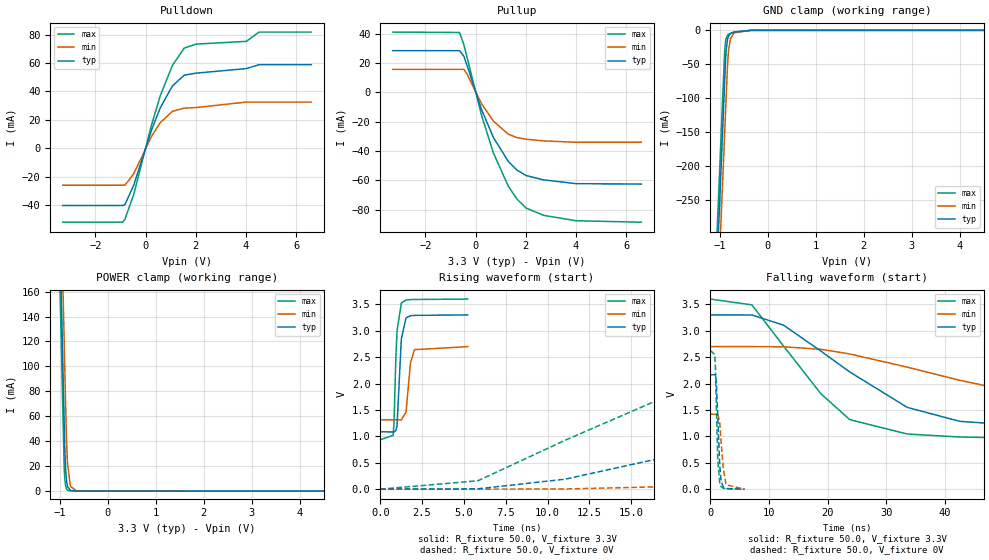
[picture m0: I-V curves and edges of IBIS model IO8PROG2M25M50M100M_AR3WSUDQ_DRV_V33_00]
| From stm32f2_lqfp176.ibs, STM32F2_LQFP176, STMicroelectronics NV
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| *** New cell (Generated with 5.14beta1 (Sep 20 2010 13:23:23))
[Model]   IO8PROG2M25M50M100M_AR3WSUDQ_DRV_V33_00
Model_type 3-state
Polarity   Non-Inverting
Enable   Active-Low
| CAP_THRESHOLD on pad IOV33 is "CMOS" :
| Rising=10.0% of vddio   Falling=90.0% of vddio
| C_comp min and max val. don't necessarily correlate with the min and max pvt
| but are the smallest and greatest pad capacitance found.
| var   typ   min   max
C_comp   2.51835pF  2.40460pF  2.66130pF
Vmeas = 1.65V   | Reference voltage for timing measurements
Cref  = 50.0pF   | Timing specification test load capacitance value
Rref  = 1.0MOhm   | Timing specification test load resistance value
Vref  = 1.65V   | Timing specification test load voltage
[Model Spec]
| variable   typ   min   max
[Temperature Range] 25.0 125.0 -40.0
| variable   typ   min   max
[Voltage Range] 3.3V 2.7V 3.6V
| variable   typ   min   max
[POWER Clamp Reference] 3.3V 2.7V 3.6V
| variable   typ   min   max
[GND Clamp Reference] 0V 0V 0V
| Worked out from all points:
|   slope of the pulldown table from 0 to 0.495 V, typ, clamps not added: 20 ohm
|   slope of the pullup table from 0 to 0.495 V, typ, clamps not added: 21.7 ohm
|   GND clamp passes 1 mA (typ) near -0.59 V on its own axis
|   POWER clamp passes 1 mA (typ) near -0.81 V on its own axis
|   rising waveform, R_fixture 50.0, V_fixture 3.3V: 20-80 % time 185ps typ, 224ps min, 174ps max; typ from 1.09 V to 3.3 V
|   falling waveform, R_fixture 50.0, V_fixture 3.3V: 20-80 % time 18.1ns typ, 35.5ns min, 11.7ns max; typ from 3.3 V to 1.09 V
|   rising waveform, R_fixture 50.0, V_fixture 0V: 20-80 % time 19.4ns typ, 44ns min, 10.8ns max; typ from 0 V to 2.17 V
|   falling waveform, R_fixture 50.0, V_fixture 0V: 20-80 % time 445ps typ, 629ps min, 359ps max; typ from 2.17 V to 0.001 V
[POWER Clamp]
-3.3V     4.117A     4.183A     4.076A
-1.09V    360mA      425.6mA    319.3mA
-1.05V    292mA      357.6mA    251.3mA
-1.01V    224mA      289.6mA    183.3mA
-910mV    53.96mA    119.6mA    18.43mA
-900mV    36.96mA    102.6mA    11.2mA
-880mV    16.97mA    68.61mA    4.141mA
-860mV    7.791mA    38.56mA    1.53mA
-840mV    3.577mA    21.53mA    565.5uA
-780mV    346.2uA    3.745mA    28.55uA
-660mV    3.242uA    113.2uA    73.21nA
6.6V      0A         0A         0A
[GND Clamp]
-3.3V     -4.156A    -4.231A    -4.108A
-1.06V    -347.5mA   -423.2mA   -300.1mA
-940mV    -143.5mA   -219.2mA   -96.09mA
-900mV    -75.54mA   -151.2mA   -30.39mA
-880mV    -41.78mA   -117.2mA   -15.62mA
-870mV    -30.28mA   -100.2mA   -12.04mA
-840mV    -13.1mA    -50.87mA   -7.186mA
-820mV    -8.54mA    -30.65mA   -5.881mA
-780mV    -4.86mA    -12.37mA   -4.416mA
-700mV    -2.552mA   -3.603mA   -2.454mA
-350mV    -11.93uA   -60.06uA   -2.46uA
6.6V      10.25nA    1.32uA     122.8pA
| variable   typ   min   max
[Pullup Reference] 3.3V 2.7V 3.6V
| variable   typ   min   max
[Pulldown Reference] 0V 0V 0V
[Pullup]
-3.3V     28.36mA    15.61mA    40.98mA
-640mV    28.36mA    15.61mA    40.72mA
-470mV    24.68mA    15.55mA    32.6mA
-350mV    18.69mA    12.65mA    24.51mA
240mV     -11.89mA   -7.822mA   -15.87mA
710mV     -30.8mA    -19.68mA   -41.36mA
1.3V      -47.02mA   -28.56mA   -63.9mA
1.65V     -53.05mA   -30.92mA   -72.82mA
2.01V     -56.71mA   -31.98mA   -78.86mA
2.7V      -59.67mA   -33.14mA   -83.8mA
4.01V     -62.27mA   -34.07mA   -87.53mA
6.6V      -62.54mA   -34.07mA   -88.51mA
[Pulldown]
-3.3V     -40.26mA   -25.94mA   -51.99mA
-910mV    -40.26mA   -25.94mA   -51.99mA
-820mV    -39.59mA   -25.94mA   -49.78mA
-470mV    -25.89mA   -17.87mA   -32.39mA
240mV     12.97mA    8.52mA     16.62mA
590mV     28.62mA    18.11mA    37.2mA
1.07V     43.85mA    26mA       58.31mA
1.54V     51.42mA    28.24mA    70.48mA
2.01V     52.82mA    28.63mA    73.27mA
4.01V     56.04mA    32.48mA    75.18mA
4.52V     58.77mA    32.48mA    81.71mA
6.6V      58.77mA    32.48mA    81.71mA
[Ramp]
dV/dt_r 1.29886V/19.39239ns 851.12089mV/43.96601ns 1.57727V/10.7657ns
dV/dt_f 1.3278V/18.13996ns 831.27765mV/35.53844ns 1.59819V/11.74015ns
R_load = 50.0
| Removed startup time: 0s 0s 0s  .
| Removed end time: 5.224ns.
[Rising Waveform]
R_fixture   = 50.0
V_fixture   = 3.3V
V_fixture_min = 2.7V
V_fixture_max = 3.6V
0s        1.087V     1.314V     936.3mV
768ps     1.084V     1.314V     1.018V
822ps     1.083V     1.314V     1.265V
930ps     1.111V     1.314V     2.478V
1.002ns   1.199V     1.313V     2.995V
1.258ns   2.844V     1.309V     3.523V
1.54ns    3.243V     1.461V     3.581V
1.806ns   3.283V     2.394V     3.589V
2.044ns   3.29V      2.641V     3.591V
5.228ns   3.299V     2.699V     3.599V
| Removed startup time: 0s 0s 0s  .
| Removed end time: 251.76ns.
[Falling Waveform]
R_fixture   = 50.0
V_fixture   = 3.3V
V_fixture_min = 2.7V
V_fixture_max = 3.6V
0s        3.3V       2.7V       3.6V
7.08ns    3.299V     2.7V       3.49V
12.48ns   3.106V     2.697V     2.711V
18.84ns   2.615V     2.649V     1.808V
23.76ns   2.22V      2.561V     1.317V
33.56ns   1.549V     2.311V     1.045V
42.52ns   1.285V     2.062V     988.4mV
58.56ns   1.161V     1.682V     953.6mV
84.6ns    1.107V     1.444V     940mV
251.8ns   1.087V     1.315V     936.3mV
| Removed startup time: 0s 0s 0s  .
| Removed end time: 243.32ns.
[Rising Waveform]
R_fixture   = 50.0
V_fixture   = 0V
V_fixture_min = 0V
V_fixture_max = 0V
0s        8.519nV    394.5nV    5.738nV
5.84ns    6.699mV    -105uV     159mV
11.08ns   190.1mV    4.116mV    929.7mV
20.44ns   843.7mV    72.35mV    2.215V
30.84ns   1.552V     251.2mV    2.546V
37.6ns    1.864V     394.3mV    2.593V
47.12ns   2.037V     608.8mV    2.617V
68.16ns   2.137V     1.023V     2.627V
93.68ns   2.159V     1.285V     2.629V
243.4ns   2.165V     1.419V     2.629V
| Removed startup time: 0s 0s 0s  .
| Removed end time: 5.82ns.
[Falling Waveform]
R_fixture   = 50.0
V_fixture   = 0V
V_fixture_min = 0V
V_fixture_max = 0V
0s        2.165V     1.419V     2.629V
770ps     2.17V      1.418V     2.548V
882ps     2.166V     1.418V     2.268V
1.038ns   2.031V     1.42V      1.555V
1.28ns    1.371V     1.428V     539.8mV
1.616ns   435.4mV    1.255V     114.2mV
1.84ns    163.9mV    915mV      49.43mV
2.206ns   43.97mV    407.4mV    17.94mV
2.688ns   13mV       83.41mV    9.189mV
5.824ns   1.034mV    941.9uV    976.4uV
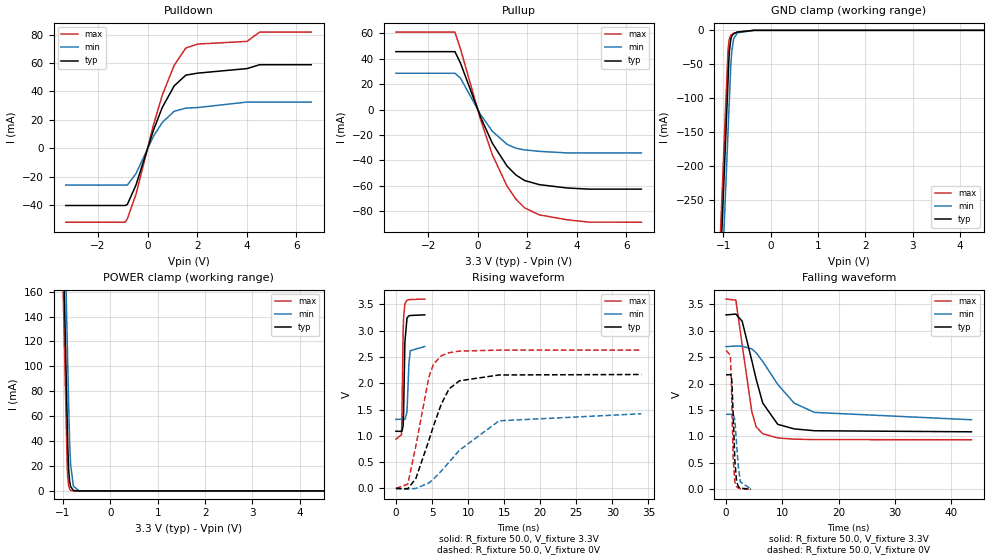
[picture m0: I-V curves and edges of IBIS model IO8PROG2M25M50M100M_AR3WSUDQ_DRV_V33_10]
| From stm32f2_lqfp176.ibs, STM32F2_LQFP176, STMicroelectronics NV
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| *** New cell (Generated with 5.14beta1 (Sep 20 2010 13:23:23))
[Model]   IO8PROG2M25M50M100M_AR3WSUDQ_DRV_V33_10
Model_type 3-state
Polarity   Non-Inverting
Enable   Active-Low
| CAP_THRESHOLD on pad IOV33 is "CMOS" :
| Rising=10.0% of vddio   Falling=90.0% of vddio
| C_comp min and max val. don't necessarily correlate with the min and max pvt
| but are the smallest and greatest pad capacitance found.
| var   typ   min   max
C_comp   2.51835pF  2.40460pF  2.66130pF
Vmeas = 1.65V   | Reference voltage for timing measurements
Cref  = 50.0pF   | Timing specification test load capacitance value
Rref  = 1.0MOhm   | Timing specification test load resistance value
Vref  = 1.65V   | Timing specification test load voltage
[Model Spec]
| variable   typ   min   max
[Temperature Range] 25.0 125.0 -40.0
| variable   typ   min   max
[Voltage Range] 3.3V 2.7V 3.6V
| variable   typ   min   max
[POWER Clamp Reference] 3.3V 2.7V 3.6V
| variable   typ   min   max
[GND Clamp Reference] 0V 0V 0V
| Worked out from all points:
|   slope of the pulldown table from 0 to 0.495 V, typ, clamps not added: 20 ohm
|   slope of the pullup table from 0 to 0.495 V, typ, clamps not added: 21.7 ohm
|   GND clamp passes 1 mA (typ) near -0.59 V on its own axis
|   POWER clamp passes 1 mA (typ) near -0.81 V on its own axis
|   rising waveform, R_fixture 50.0, V_fixture 3.3V: 20-80 % time 185ps typ, 224ps min, 175ps max; typ from 1.09 V to 3.3 V
|   falling waveform, R_fixture 50.0, V_fixture 3.3V: 20-80 % time 3.18ns typ, 6.14ns min, 2.09ns max; typ from 3.3 V to 1.09 V
|   rising waveform, R_fixture 50.0, V_fixture 0V: 20-80 % time 3.25ns typ, 6.06ns min, 2.15ns max; typ from 0 V to 2.17 V
|   falling waveform, R_fixture 50.0, V_fixture 0V: 20-80 % time 445ps typ, 628ps min, 360ps max; typ from 2.17 V to 0.001 V
[POWER Clamp]
-3.3V     4.117A     4.183A     4.076A
-1.09V    360mA      425.6mA    319.3mA
-1.05V    292mA      357.6mA    251.3mA
-1.01V    224mA      289.6mA    183.3mA
-910mV    53.96mA    119.6mA    18.43mA
-900mV    36.96mA    102.6mA    11.2mA
-880mV    16.97mA    68.61mA    4.141mA
-860mV    7.791mA    38.56mA    1.53mA
-840mV    3.577mA    21.53mA    565.5uA
-780mV    346.2uA    3.745mA    28.55uA
-660mV    3.242uA    113.2uA    73.21nA
6.6V      0A         0A         0A
[GND Clamp]
-3.3V     -4.156A    -4.231A    -4.108A
-1.06V    -347.5mA   -423.2mA   -300.1mA
-940mV    -143.5mA   -219.2mA   -96.09mA
-900mV    -75.54mA   -151.2mA   -30.39mA
-880mV    -41.78mA   -117.2mA   -15.62mA
-870mV    -30.28mA   -100.2mA   -12.04mA
-840mV    -13.1mA    -50.87mA   -7.186mA
-820mV    -8.54mA    -30.65mA   -5.881mA
-780mV    -4.86mA    -12.37mA   -4.416mA
-700mV    -2.552mA   -3.603mA   -2.454mA
-350mV    -11.93uA   -60.06uA   -2.46uA
6.6V      10.25nA    1.32uA     122.8pA
| variable   typ   min   max
[Pullup Reference] 3.3V 2.7V 3.6V
| variable   typ   min   max
[Pulldown Reference] 0V 0V 0V
[Pullup]
-3.3V     45.5mA     28.54mA    60.89mA
-920mV    45.5mA     28.54mA    60.89mA
-700mV    36.73mA    24.81mA    47.95mA
120mV     -6.142mA   -4.065mA   -8.189mA
590mV     -26.5mA    -17.07mA   -35.52mA
1.18V     -44.36mA   -27.27mA   -60.11mA
1.54V     -51.43mA   -30.39mA   -70.35mA
1.89V     -55.75mA   -31.69mA   -77.18mA
2.48V     -58.98mA   -32.83mA   -82.75mA
3.6V      -61.62mA   -34.07mA   -86.61mA
4.49V     -62.54mA   -34.07mA   -88.47mA
6.6V      -62.54mA   -34.07mA   -88.51mA
[Pulldown]
-3.3V     -40.26mA   -25.94mA   -51.99mA
-910mV    -40.26mA   -25.94mA   -51.99mA
-820mV    -39.59mA   -25.94mA   -49.78mA
-470mV    -25.89mA   -17.87mA   -32.39mA
240mV     12.97mA    8.52mA     16.62mA
590mV     28.62mA    18.11mA    37.2mA
1.07V     43.85mA    26mA       58.31mA
1.54V     51.42mA    28.24mA    70.48mA
2.01V     52.82mA    28.63mA    73.27mA
4.01V     56.04mA    32.48mA    75.18mA
4.52V     58.77mA    32.48mA    81.71mA
6.6V      58.77mA    32.48mA    81.71mA
[Ramp]
dV/dt_r 1.29886V/3.25391ns 851.30591mV/6.06174ns 1.57727V/2.15285ns
dV/dt_f 1.32782V/3.18087ns 831.60152mV/6.14857ns 1.59819V/2.0877ns
R_load = 50.0
| Removed startup time: 0s 0s 0s  .
| Removed end time: 3.993ns.
[Rising Waveform]
R_fixture   = 50.0
V_fixture   = 3.3V
V_fixture_min = 2.7V
V_fixture_max = 3.6V
0s        1.087V     1.314V     936.3mV
769ps     1.084V     1.314V     1.02V
823ps     1.083V     1.314V     1.275V
997ps     1.189V     1.313V     2.967V
1.066ns   1.46V      1.313V     3.244V
1.242ns   2.778V     1.309V     3.509V
1.536ns   3.239V     1.454V     3.577V
1.799ns   3.28V      2.377V     3.585V
1.992ns   3.286V     2.618V     3.589V
3.995ns   3.298V     2.697V     3.598V
| Removed startup time: 0s 0s 0s  .
| Removed end time: 43.615ns.
[Falling Waveform]
R_fixture   = 50.0
V_fixture   = 3.3V
V_fixture_min = 2.7V
V_fixture_max = 3.6V
0s        3.3V       2.7V       3.6V
1.745ns   3.316V     2.711V     3.58V
2.865ns   3.181V     2.707V     2.734V
4.58ns    2.435V     2.657V     1.467V
5.345ns   2.087V     2.583V     1.181V
6.515ns   1.633V     2.419V     1.051V
9.185ns   1.229V     1.985V     970.5mV
12.11ns   1.142V     1.629V     947.7mV
15.74ns   1.107V     1.454V     939.6mV
43.63ns   1.087V     1.315V     936.3mV
| Removed startup time: 0s 0s 0s  .
| Removed end time: 33.995ns.
[Rising Waveform]
R_fixture   = 50.0
V_fixture   = 0V
V_fixture_min = 0V
V_fixture_max = 0V
0s        8.508nV    394.6nV    5.727nV
1.64ns    -4.182mV   -13.42mV   81.4mV
2.755ns   186.5mV    726.8uV    802.5mV
4.55ns    905.9mV    102.6mV    2.11V
5.21ns    1.189V     179.3mV    2.365V
6.28ns    1.6V       329.6mV    2.52V
7.35ns    1.889V     497.1mV    2.578V
8.795ns   2.045V     726.1mV    2.61V
14.29ns   2.156V     1.285V     2.628V
34.01ns   2.165V     1.419V     2.629V
| Removed startup time: 0s 0s 0s  .
| Removed end time: 4.439ns.
[Falling Waveform]
R_fixture   = 50.0
V_fixture   = 0V
V_fixture_min = 0V
V_fixture_max = 0V
0s        2.165V     1.419V     2.629V
779ps     2.17V      1.418V     2.532V
943ps     2.14V      1.419V     2.038V
1.035ns   2.034V     1.42V      1.569V
1.267ns   1.413V     1.427V     577.9mV
1.564ns   543.1mV    1.314V     142.9mV
1.862ns   150.9mV    877.4mV    48.17mV
2.197ns   46.75mV    416.2mV    20.44mV
2.544ns   19.06mV    138.6mV    9.23mV
4.441ns   1.497mV    2.846mV    977.3uV
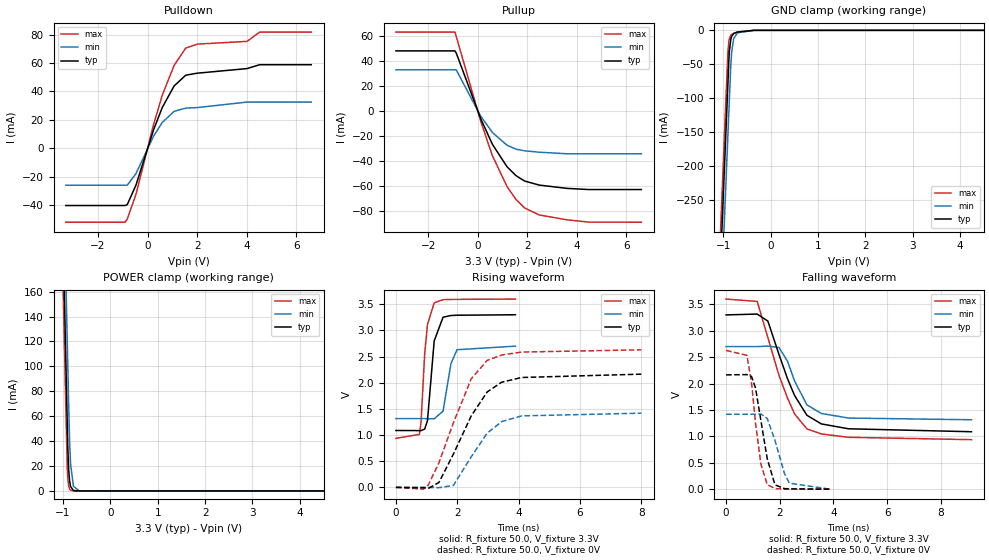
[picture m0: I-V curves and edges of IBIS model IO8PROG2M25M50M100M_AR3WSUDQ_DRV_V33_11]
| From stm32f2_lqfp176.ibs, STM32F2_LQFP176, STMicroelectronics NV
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| *** New cell (Generated with 5.14beta1 (Sep 20 2010 13:23:23))
[Model]   IO8PROG2M25M50M100M_AR3WSUDQ_DRV_V33_11
Model_type 3-state
Polarity   Non-Inverting
Enable   Active-Low
| CAP_THRESHOLD on pad IOV33 is "CMOS" :
| Rising=10.0% of vddio   Falling=90.0% of vddio
| C_comp min and max val. don't necessarily correlate with the min and max pvt
| but are the smallest and greatest pad capacitance found.
| var   typ   min   max
C_comp   2.51835pF  2.40455pF  2.66130pF
Vmeas = 1.65V   | Reference voltage for timing measurements
Cref  = 50.0pF   | Timing specification test load capacitance value
Rref  = 1.0MOhm   | Timing specification test load resistance value
Vref  = 1.65V   | Timing specification test load voltage
[Model Spec]
| variable   typ   min   max
[Temperature Range] 25.0 125.0 -40.0
| variable   typ   min   max
[Voltage Range] 3.3V 2.7V 3.6V
| variable   typ   min   max
[POWER Clamp Reference] 3.3V 2.7V 3.6V
| variable   typ   min   max
[GND Clamp Reference] 0V 0V 0V
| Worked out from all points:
|   slope of the pulldown table from 0 to 0.495 V, typ, clamps not added: 20 ohm
|   slope of the pullup table from 0 to 0.495 V, typ, clamps not added: 21.7 ohm
|   GND clamp passes 1 mA (typ) near -0.59 V on its own axis
|   POWER clamp passes 1 mA (typ) near -0.81 V on its own axis
|   rising waveform, R_fixture 50.0, V_fixture 3.3V: 20-80 % time 188ps typ, 225ps min, 176ps max; typ from 1.09 V to 3.3 V
|   falling waveform, R_fixture 50.0, V_fixture 3.3V: 20-80 % time 1.04ns typ, 731ps min, 1.05ns max; typ from 3.3 V to 1.09 V
|   rising waveform, R_fixture 50.0, V_fixture 0V: 20-80 % time 1.12ns typ, 970ps min, 1.04ns max; typ from 0 V to 2.16 V
|   falling waveform, R_fixture 50.0, V_fixture 0V: 20-80 % time 420ps typ, 489ps min, 355ps max; typ from 2.17 V to 0.001 V
[POWER Clamp]
-3.3V     4.117A     4.183A     4.076A
-1.09V    360mA      425.6mA    319.3mA
-1.05V    292mA      357.6mA    251.3mA
-1.01V    224mA      289.6mA    183.3mA
-910mV    53.96mA    119.6mA    18.43mA
-900mV    36.96mA    102.6mA    11.2mA
-880mV    16.97mA    68.61mA    4.141mA
-860mV    7.791mA    38.56mA    1.53mA
-840mV    3.577mA    21.53mA    565.5uA
-780mV    346.2uA    3.745mA    28.55uA
-660mV    3.242uA    113.2uA    73.21nA
6.6V      0A         0A         0A
[GND Clamp]
-3.3V     -4.156A    -4.231A    -4.108A
-1.06V    -347.5mA   -423.2mA   -300.1mA
-940mV    -143.5mA   -219.2mA   -96.09mA
-900mV    -75.54mA   -151.2mA   -30.39mA
-880mV    -41.78mA   -117.2mA   -15.62mA
-870mV    -30.28mA   -100.2mA   -12.04mA
-840mV    -13.1mA    -50.87mA   -7.186mA
-820mV    -8.54mA    -30.65mA   -5.881mA
-780mV    -4.86mA    -12.37mA   -4.416mA
-700mV    -2.552mA   -3.603mA   -2.454mA
-350mV    -11.93uA   -60.06uA   -2.46uA
6.6V      10.25nA    1.32uA     122.8pA
| variable   typ   min   max
[Pullup Reference] 3.3V 2.7V 3.6V
| variable   typ   min   max
[Pulldown Reference] 0V 0V 0V
[Pullup]
-3.3V     47.82mA    32.75mA    62.76mA
-920mV    47.82mA    32.75mA    62.76mA
-870mV    46.26mA    32.75mA    59.5mA
120mV     -6.142mA   -4.065mA   -8.189mA
590mV     -26.5mA    -17.07mA   -35.52mA
1.18V     -44.36mA   -27.27mA   -60.11mA
1.54V     -51.43mA   -30.39mA   -70.35mA
1.89V     -55.75mA   -31.69mA   -77.18mA
2.48V     -58.98mA   -32.83mA   -82.75mA
3.6V      -61.62mA   -34.07mA   -86.61mA
4.49V     -62.54mA   -34.07mA   -88.47mA
6.6V      -62.54mA   -34.07mA   -88.51mA
[Pulldown]
-3.3V     -40.26mA   -25.94mA   -51.99mA
-910mV    -40.26mA   -25.94mA   -51.99mA
-820mV    -39.59mA   -25.94mA   -49.78mA
-470mV    -25.89mA   -17.87mA   -32.39mA
240mV     12.97mA    8.52mA     16.62mA
590mV     28.62mA    18.11mA    37.2mA
1.07V     43.85mA    26mA       58.31mA
1.54V     51.42mA    28.24mA    70.48mA
2.01V     52.82mA    28.63mA    73.27mA
4.01V     56.04mA    32.48mA    75.18mA
4.52V     58.77mA    32.48mA    81.71mA
6.6V      58.77mA    32.48mA    81.71mA
[Ramp]
dV/dt_r 1.29886V/1.12517ns 851.30674mV/971.89074ps 1.57727V/1.04388ns
dV/dt_f 1.32782V/1.03911ns 831.60268mV/731.70994ps 1.59819V/1.05301ns
R_load = 50.0
| Removed startup time: 0s 0s 0s  .
| Removed end time: 3.893ns.
[Rising Waveform]
R_fixture   = 50.0
V_fixture   = 3.3V
V_fixture_min = 2.7V
V_fixture_max = 3.6V
0s        1.087V     1.314V     936.3mV
766ps     1.085V     1.314V     1.013V
819ps     1.084V     1.314V     1.245V
938ps     1.115V     1.314V     2.553V
1.029ns   1.274V     1.313V     3.111V
1.248ns   2.799V     1.31V      3.527V
1.537ns   3.252V     1.457V     3.587V
1.793ns   3.285V     2.363V     3.592V
1.992ns   3.29V      2.631V     3.593V
3.895ns   3.299V     2.699V     3.599V
| Removed startup time: 0s 0s 0s  .
| Removed end time: 9.135ns.
[Falling Waveform]
R_fixture   = 50.0
V_fixture   = 3.3V
V_fixture_min = 2.7V
V_fixture_max = 3.6V
0s        3.3V       2.7V       3.6V
1.159ns   3.316V     2.7V       3.555V
1.557ns   3.183V     2.71V      2.871V
1.972ns   2.549V     2.682V     2.153V
2.288ns   2.092V     2.423V     1.726V
2.551ns   1.774V     2.049V     1.425V
3.011ns   1.399V     1.596V     1.142V
3.549ns   1.236V     1.434V     1.046V
4.558ns   1.144V     1.347V     982.8mV
9.137ns   1.088V     1.315V     937.9mV
| Removed startup time: 0s 0s 0s  .
| Removed end time: 8.001ns.
[Rising Waveform]
R_fixture   = 50.0
V_fixture   = 0V
V_fixture_min = 0V
V_fixture_max = 0V
0s        8.508nV    394.5nV    5.742nV
900ps     -6.906mV   62.6uV     -34.39mV
1.061ns   -18.3mV    221.9uV    50.88mV
1.402ns   93.66mV    -6.014mV   470.2mV
1.873ns   634.6mV    36.03mV    1.232V
2.456ns   1.367V     585mV      2.075V
2.977ns   1.824V     1.037V     2.427V
3.445ns   2.009V     1.256V     2.529V
4.098ns   2.1V       1.366V     2.586V
8.003ns   2.164V     1.418V     2.629V
| Removed startup time: 0s 0s 0s  .
| Removed end time: 3.867ns.
[Falling Waveform]
R_fixture   = 50.0
V_fixture   = 0V
V_fixture_min = 0V
V_fixture_max = 0V
0s        2.165V     1.419V     2.629V
778ps     2.17V      1.418V     2.533V
948ps     2.134V     1.419V     2.016V
1.097ns   1.917V     1.421V     1.254V
1.296ns   1.305V     1.424V     477.8mV
1.533ns   578.1mV    1.339V     87.47mV
1.822ns   81.67mV    924.5mV    11.78mV
2.171ns   11.58mV    303.5mV    4.225mV
2.357ns   6.341mV    114.1mV    3.342mV
3.869ns   864uV      775.3uV    719.2uV
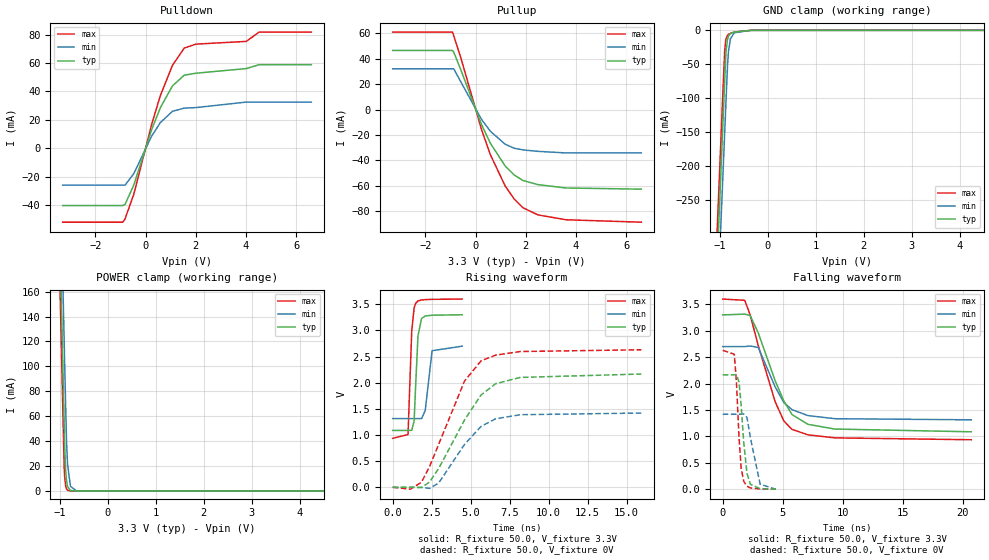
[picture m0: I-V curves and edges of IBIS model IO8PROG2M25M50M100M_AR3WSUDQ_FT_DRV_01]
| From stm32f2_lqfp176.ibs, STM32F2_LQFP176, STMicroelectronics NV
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| *** New cell (Generated with 5.14beta1 (Sep 20 2010 13:23:23))
[Model]   IO8PROG2M25M50M100M_AR3WSUDQ_FT_DRV_01
Model_type 3-state
Polarity   Non-Inverting
Enable   Active-Low
| CAP_THRESHOLD on pad IOV33 is "CMOS" :
| Rising=10.0% of vddio   Falling=90.0% of vddio
| C_comp min and max val. don't necessarily correlate with the min and max pvt
| but are the smallest and greatest pad capacitance found.
| var   typ   min   max
C_comp   2.51760pF  2.40375pF  2.66060pF
Vmeas = 1.65V   | Reference voltage for timing measurements
Cref  = 50.0pF   | Timing specification test load capacitance value
Rref  = 10.0MOhm   | Timing specification test load resistance value
Vref  = 1.65V   | Timing specification test load voltage
[Model Spec]
| variable   typ   min   max
[Temperature Range] 25.0 125.0 -40.0
| variable   typ   min   max
[Voltage Range] 3.3V 2.7V 3.6V
| variable   typ   min   max
[POWER Clamp Reference] 3.3V 2.7V 3.6V
| variable   typ   min   max
[GND Clamp Reference] 0V 0V 0V
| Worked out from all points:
|   slope of the pulldown table from 0 to 0.495 V, typ, clamps not added: 20 ohm
|   slope of the pullup table from 0 to 0.495 V, typ, clamps not added: 21.7 ohm
|   GND clamp passes 1 mA (typ) near -0.59 V on its own axis
|   POWER clamp passes 1 mA (typ) near -0.81 V on its own axis
|   rising waveform, R_fixture 50.0, V_fixture 3.3V: 20-80 % time 186ps typ, 225ps min, 174ps max; typ from 1.09 V to 3.3 V
|   falling waveform, R_fixture 50.0, V_fixture 3.3V: 20-80 % time 2.29ns typ, 1.78ns min, 2.13ns max; typ from 3.3 V to 1.09 V
|   rising waveform, R_fixture 50.0, V_fixture 0V: 20-80 % time 2.49ns typ, 2.08ns min, 2.19ns max; typ from 0 V to 2.17 V
|   falling waveform, R_fixture 50.0, V_fixture 0V: 20-80 % time 445ps typ, 627ps min, 360ps max; typ from 2.17 V to 0.001 V
[POWER Clamp]
-3.3V     4.117A     4.183A     4.076A
-1.09V    360mA      425.6mA    319.3mA
-1.05V    292mA      357.6mA    251.3mA
-1.01V    224mA      289.6mA    183.3mA
-910mV    53.96mA    119.6mA    18.43mA
-900mV    36.96mA    102.6mA    11.2mA
-880mV    16.97mA    68.61mA    4.141mA
-860mV    7.791mA    38.56mA    1.53mA
-840mV    3.577mA    21.53mA    565.5uA
-780mV    346.2uA    3.745mA    28.55uA
-660mV    3.242uA    113.2uA    73.21nA
6.6V      0A         0A         0A
[GND Clamp]
-3.3V     -4.156A    -4.231A    -4.108A
-1.06V    -347.5mA   -423.2mA   -300.1mA
-940mV    -143.5mA   -219.2mA   -96.09mA
-900mV    -75.54mA   -151.2mA   -30.39mA
-880mV    -41.78mA   -117.2mA   -15.62mA
-870mV    -30.28mA   -100.2mA   -12.04mA
-840mV    -13.1mA    -50.87mA   -7.186mA
-820mV    -8.54mA    -30.65mA   -5.881mA
-780mV    -4.86mA    -12.37mA   -4.416mA
-700mV    -2.552mA   -3.603mA   -2.454mA
-350mV    -11.93uA   -60.06uA   -2.46uA
6.6V      10.25nA    1.32uA     122.8pA
| variable   typ   min   max
[Pullup Reference] 3.3V 2.7V 3.6V
| variable   typ   min   max
[Pulldown Reference] 0V 0V 0V
[Pullup]
-3.3V     46.47mA    32.09mA    60.92mA
-920mV    46.47mA    32.09mA    60.92mA
-870mV    45.1mA     32.09mA    58.12mA
-590mV    31.41mA    21.87mA    40.86mA
240mV     -11.89mA   -7.822mA   -15.87mA
590mV     -26.5mA    -17.07mA   -35.52mA
1.18V     -44.36mA   -27.27mA   -60.11mA
1.54V     -51.43mA   -30.39mA   -70.35mA
1.89V     -55.75mA   -31.69mA   -77.18mA
2.48V     -58.98mA   -32.83mA   -82.75mA
3.6V      -61.62mA   -34.07mA   -86.61mA
6.6V      -62.54mA   -34.07mA   -88.51mA
[Pulldown]
-3.3V     -40.26mA   -25.94mA   -51.99mA
-910mV    -40.26mA   -25.94mA   -51.99mA
-820mV    -39.59mA   -25.94mA   -49.78mA
-470mV    -25.89mA   -17.87mA   -32.39mA
240mV     12.97mA    8.52mA     16.62mA
590mV     28.62mA    18.11mA    37.2mA
1.07V     43.85mA    26mA       58.31mA
1.54V     51.42mA    28.24mA    70.48mA
2.01V     52.82mA    28.63mA    73.27mA
4.01V     56.05mA    32.5mA     75.18mA
4.52V     58.79mA    32.5mA     81.73mA
6.6V      58.79mA    32.5mA     81.73mA
[Ramp]
dV/dt_r 1.29886V/2.49086ns 851.46592mV/2.08317ns 1.57727V/2.18543ns
dV/dt_f 1.32782V/2.29014ns 831.60246mV/1.77762ns 1.59819V/2.12776ns
R_load = 50.0
| Removed startup time: 0s 0s 0s  .
| Removed end time: 4.455ns.
[Rising Waveform]
R_fixture   = 50.0
V_fixture   = 3.3V
V_fixture_min = 2.7V
V_fixture_max = 3.6V
0s        1.087V     1.314V     936.3mV
982ps     1.087V     1.314V     1.008V
1.221ns   1.089V     1.314V     2.992V
1.375ns   1.268V     1.314V     3.428V
1.473ns   1.947V     1.314V     3.516V
1.621ns   2.898V     1.313V     3.562V
1.853ns   3.226V     1.312V     3.581V
2.086ns   3.275V     1.468V     3.587V
2.527ns   3.289V     2.611V     3.593V
4.457ns   3.298V     2.697V     3.598V
| Removed startup time: 0s 0s 0s  .
| Removed end time: 20.695ns.
[Falling Waveform]
R_fixture   = 50.0
V_fixture   = 3.3V
V_fixture_min = 2.7V
V_fixture_max = 3.6V
0s        3.3V       2.7V       3.6V
1.835ns   3.315V     2.701V     3.577V
2.28ns    3.29V      2.711V     3.304V
2.955ns   2.962V     2.685V     2.724V
4.365ns   2.055V     1.938V     1.657V
5.095ns   1.667V     1.64V      1.29V
5.77ns    1.413V     1.506V     1.132V
7.105ns   1.228V     1.394V     1.029V
9.345ns   1.139V     1.335V     972.2mV
20.7ns    1.087V     1.314V     936.6mV
| Removed startup time: 0s 0s 0s  .
| Removed end time: 15.94ns.
[Rising Waveform]
R_fixture   = 50.0
V_fixture   = 0V
V_fixture_min = 0V
V_fixture_max = 0V
0s        8.515nV    394.6nV    5.739nV
1.135ns   -325.3uV   -6.741uV   -35.93mV
1.845ns   -4.417mV   -2.031mV   97.66mV
2.36ns    99.51mV    -20.99mV   392.9mV
2.95ns    359.6mV    80.93mV    822mV
4.605ns   1.285V     818.1mV    2.029V
5.67ns    1.765V     1.164V     2.418V
6.6ns     1.979V     1.309V     2.526V
8.18ns    2.1V       1.387V     2.595V
15.95ns   2.165V     1.419V     2.629V
| Removed startup time: 0s 0s 0s  .
| Removed end time: 4.406ns.
[Falling Waveform]
R_fixture   = 50.0
V_fixture   = 0V
V_fixture_min = 0V
V_fixture_max = 0V
0s        2.165V     1.419V     2.629V
962ps     2.166V     1.419V     2.556V
1.145ns   2.171V     1.419V     2.025V
1.359ns   2.026V     1.418V     975.4mV
1.535ns   1.588V     1.42V      401.3mV
1.75ns    887.1mV    1.426V     150.5mV
2.02ns    299.5mV    1.359V     55.23mV
2.313ns   92.81mV    966.3mV    24.03mV
3.118ns   8.071mV    93.93mV    3.788mV
4.408ns   1.425mV    1.787mV    1.035mV
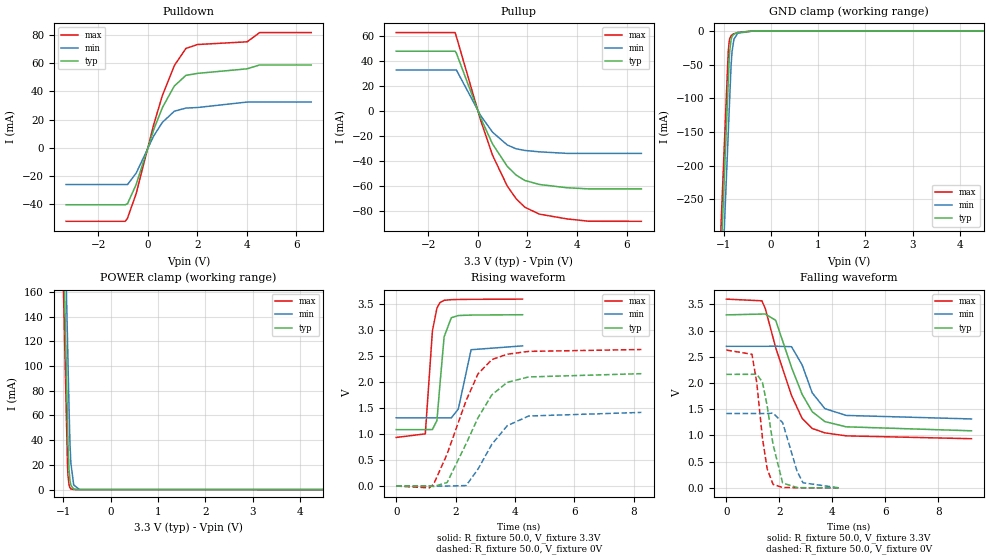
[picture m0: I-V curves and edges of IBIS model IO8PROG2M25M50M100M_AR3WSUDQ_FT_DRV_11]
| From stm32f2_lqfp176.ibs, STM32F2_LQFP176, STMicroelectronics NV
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| *** New cell (Generated with 5.14beta1 (Sep 20 2010 13:23:23))
[Model]   IO8PROG2M25M50M100M_AR3WSUDQ_FT_DRV_11
Model_type 3-state
Polarity   Non-Inverting
Enable   Active-Low
| CAP_THRESHOLD on pad IOV33 is "CMOS" :
| Rising=10.0% of vddio   Falling=90.0% of vddio
| C_comp min and max val. don't necessarily correlate with the min and max pvt
| but are the smallest and greatest pad capacitance found.
| var   typ   min   max
C_comp   2.51760pF  2.40375pF  2.66055pF
Vmeas = 1.65V   | Reference voltage for timing measurements
Cref  = 50.0pF   | Timing specification test load capacitance value
Rref  = 10.0MOhm   | Timing specification test load resistance value
Vref  = 1.65V   | Timing specification test load voltage
[Model Spec]
| variable   typ   min   max
[Temperature Range] 25.0 125.0 -40.0
| variable   typ   min   max
[Voltage Range] 3.3V 2.7V 3.6V
| variable   typ   min   max
[POWER Clamp Reference] 3.3V 2.7V 3.6V
| variable   typ   min   max
[GND Clamp Reference] 0V 0V 0V
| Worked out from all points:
|   slope of the pulldown table from 0 to 0.495 V, typ, clamps not added: 20 ohm
|   slope of the pullup table from 0 to 0.495 V, typ, clamps not added: 21.7 ohm
|   GND clamp passes 1 mA (typ) near -0.59 V on its own axis
|   POWER clamp passes 1 mA (typ) near -0.81 V on its own axis
|   rising waveform, R_fixture 50.0, V_fixture 3.3V: 20-80 % time 188ps typ, 225ps min, 176ps max; typ from 1.09 V to 3.3 V
|   falling waveform, R_fixture 50.0, V_fixture 3.3V: 20-80 % time 1.04ns typ, 731ps min, 1.05ns max; typ from 3.3 V to 1.09 V
|   rising waveform, R_fixture 50.0, V_fixture 0V: 20-80 % time 1.13ns typ, 972ps min, 1.04ns max; typ from 0 V to 2.16 V
|   falling waveform, R_fixture 50.0, V_fixture 0V: 20-80 % time 421ps typ, 490ps min, 355ps max; typ from 2.17 V to 0.001 V
[POWER Clamp]
-3.3V     4.117A     4.183A     4.076A
-1.09V    360mA      425.6mA    319.3mA
-1.05V    292mA      357.6mA    251.3mA
-1.01V    224mA      289.6mA    183.3mA
-910mV    53.96mA    119.6mA    18.43mA
-900mV    36.96mA    102.6mA    11.2mA
-880mV    16.97mA    68.61mA    4.141mA
-860mV    7.791mA    38.56mA    1.53mA
-840mV    3.577mA    21.53mA    565.5uA
-780mV    346.2uA    3.745mA    28.55uA
-660mV    3.242uA    113.2uA    73.21nA
6.6V      0A         0A         0A
[GND Clamp]
-3.3V     -4.156A    -4.231A    -4.108A
-1.06V    -347.5mA   -423.2mA   -300.1mA
-940mV    -143.5mA   -219.2mA   -96.09mA
-900mV    -75.54mA   -151.2mA   -30.39mA
-880mV    -41.78mA   -117.2mA   -15.62mA
-870mV    -30.28mA   -100.2mA   -12.04mA
-840mV    -13.1mA    -50.87mA   -7.186mA
-820mV    -8.54mA    -30.65mA   -5.881mA
-780mV    -4.86mA    -12.37mA   -4.416mA
-700mV    -2.552mA   -3.603mA   -2.454mA
-350mV    -11.93uA   -60.06uA   -2.46uA
6.6V      10.25nA    1.32uA     122.8pA
| variable   typ   min   max
[Pullup Reference] 3.3V 2.7V 3.6V
| variable   typ   min   max
[Pulldown Reference] 0V 0V 0V
[Pullup]
-3.3V     47.83mA    32.77mA    62.77mA
-920mV    47.83mA    32.77mA    62.77mA
-870mV    46.27mA    32.77mA    59.51mA
120mV     -6.142mA   -4.065mA   -8.189mA
590mV     -26.5mA    -17.07mA   -35.52mA
1.18V     -44.36mA   -27.27mA   -60.11mA
1.54V     -51.43mA   -30.39mA   -70.35mA
1.89V     -55.75mA   -31.69mA   -77.18mA
2.48V     -58.98mA   -32.83mA   -82.75mA
3.6V      -61.62mA   -34.07mA   -86.61mA
4.49V     -62.54mA   -34.07mA   -88.47mA
6.6V      -62.54mA   -34.07mA   -88.51mA
[Pulldown]
-3.3V     -40.26mA   -25.94mA   -51.99mA
-910mV    -40.26mA   -25.94mA   -51.99mA
-820mV    -39.59mA   -25.94mA   -49.78mA
-470mV    -25.89mA   -17.87mA   -32.39mA
240mV     12.97mA    8.52mA     16.62mA
590mV     28.62mA    18.11mA    37.2mA
1.07V     43.85mA    26mA       58.31mA
1.54V     51.42mA    28.24mA    70.48mA
2.01V     52.82mA    28.63mA    73.27mA
4.01V     56.05mA    32.5mA     75.18mA
4.52V     58.79mA    32.5mA     81.73mA
6.6V      58.79mA    32.5mA     81.73mA
[Ramp]
dV/dt_r 1.29886V/1.12563ns 851.30674mV/972.54594ps 1.57727V/1.04409ns
dV/dt_f 1.32782V/1.03909ns 831.60268mV/732.06279ps 1.59819V/1.05292ns
R_load = 50.0
| Removed startup time: 0s 0s 0s  .
| Removed end time: 4.257ns.
[Rising Waveform]
R_fixture   = 50.0
V_fixture   = 3.3V
V_fixture_min = 2.7V
V_fixture_max = 3.6V
0s        1.087V     1.314V     936.3mV
981ps     1.087V     1.314V     1.005V
1.221ns   1.089V     1.314V     2.988V
1.373ns   1.262V     1.314V     3.425V
1.471ns   1.933V     1.314V     3.53V
1.615ns   2.873V     1.313V     3.576V
1.857ns   3.241V     1.313V     3.589V
2.093ns   3.283V     1.482V     3.592V
2.524ns   3.292V     2.625V     3.595V
4.259ns   3.299V     2.699V     3.599V
| Removed startup time: 0s 0s 0s  .
| Removed end time: 9.251ns.
[Falling Waveform]
R_fixture   = 50.0
V_fixture   = 3.3V
V_fixture_min = 2.7V
V_fixture_max = 3.6V
0s        3.3V       2.7V       3.6V
1.342ns   3.315V     2.7V       3.568V
1.469ns   3.316V     2.7V       3.424V
1.863ns   3.196V     2.702V     2.674V
2.461ns   2.298V     2.693V     1.761V
2.86ns    1.785V     2.346V     1.327V
3.243ns   1.452V     1.811V     1.133V
3.719ns   1.265V     1.512V     1.05V
4.523ns   1.165V     1.382V     992.6mV
9.253ns   1.089V     1.315V     938mV
| Removed startup time: 0s 0s 0s  .
| Removed end time: 8.262ns.
[Rising Waveform]
R_fixture   = 50.0
V_fixture   = 0V
V_fixture_min = 0V
V_fixture_max = 0V
0s        8.532nV    394.6nV    5.739nV
1.116ns   127.2uV    -5.938uV   -34.54mV
1.266ns   -8.31mV    10.45uV    39.45mV
1.716ns   67.83mV    205.7uV    616.9mV
2.358ns   817.8mV    9.463mV    1.649V
2.759ns   1.317V     328mV      2.162V
3.224ns   1.756V     804.3mV    2.435V
3.741ns   1.996V     1.161V     2.538V
4.466ns   2.101V     1.349V     2.593V
8.264ns   2.164V     1.418V     2.629V
| Removed startup time: 0s 0s 0s  .
| Removed end time: 4.248ns.
[Falling Waveform]
R_fixture   = 50.0
V_fixture   = 0V
V_fixture_min = 0V
V_fixture_max = 0V
0s        2.165V     1.419V     2.629V
966ps     2.166V     1.419V     2.549V
1.147ns   2.17V      1.419V     2.014V
1.362ns   2.019V     1.418V     952.5mV
1.54ns    1.568V     1.42V      366.8mV
1.763ns   828.7mV    1.425V     66.99mV
2.125ns   93.22mV    1.246V     7.797mV
2.673ns   6.483mV    313.1mV    3.051mV
2.894ns   4.122mV    97.65mV    2.604mV
4.25ns    1.028mV    1.074mV    793.3uV
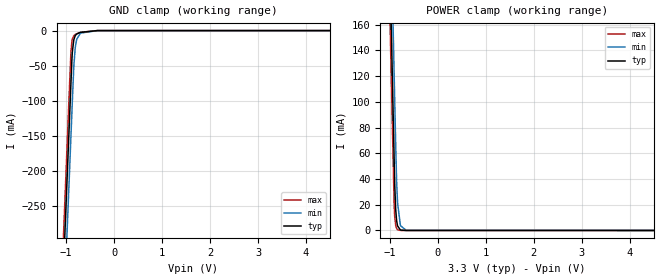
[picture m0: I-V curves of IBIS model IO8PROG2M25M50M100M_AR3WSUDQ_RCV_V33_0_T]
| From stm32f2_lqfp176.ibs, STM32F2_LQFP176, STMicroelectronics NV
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| *** New cell (Generated with 5.14beta1 (Sep 20 2010 13:23:23))
[Model]   IO8PROG2M25M50M100M_AR3WSUDQ_RCV_V33_0_T
Model_type Input
Polarity   Non-Inverting
Enable   Active-Low
| CAP_THRESHOLD on pad IOV33 is "CMOS" :
| Rising=10.0% of vddio   Falling=90.0% of vddio
| C_comp min and max val. don't necessarily correlate with the min and max pvt
| but are the smallest and greatest pad capacitance found.
| var   typ   min   max
C_comp   2.53650pF  2.40960pF  2.66950pF
Vinl = 800.0mV | Dummy value overriden by next lines
Vinh = 2.00V | Dummy value overriden by next lines
[Model Spec]
| TIME_THRESHOLD on pin ZIV33 is "CORE" :
| Rising=40.0% of vddio   Falling=60.0% of vddio
Vinl 1.25450V 1.03850V 1.36250V
Vinh 1.66150V 1.36950V 1.82450V
| variable   typ   min   max
[Temperature Range] 25.0 125.0 -40.0
| variable   typ   min   max
[Voltage Range] 3.3V 2.7V 3.6V
| variable   typ   min   max
[POWER Clamp Reference] 3.3V 2.7V 3.6V
| variable   typ   min   max
[GND Clamp Reference] 0V 0V 0V
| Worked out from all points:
|   GND clamp passes 1 mA (typ) near -0.59 V on its own axis
|   POWER clamp passes 1 mA (typ) near -0.81 V on its own axis
[POWER Clamp]
-3.3V     4.117A     4.183A     4.076A
-1.09V    360mA      425.6mA    319.3mA
-1.05V    292mA      357.6mA    251.3mA
-1.01V    224mA      289.6mA    183.3mA
-910mV    53.96mA    119.6mA    18.43mA
-900mV    36.96mA    102.6mA    11.2mA
-880mV    16.97mA    68.61mA    4.141mA
-860mV    7.791mA    38.56mA    1.53mA
-840mV    3.577mA    21.53mA    565.5uA
-780mV    346.2uA    3.745mA    28.55uA
-660mV    3.242uA    113.2uA    73.21nA
6.6V      0A         0A         0A
[GND Clamp]
-3.3V     -4.156A    -4.231A    -4.108A
-1.06V    -347.5mA   -423.2mA   -300.1mA
-940mV    -143.5mA   -219.2mA   -96.09mA
-900mV    -75.54mA   -151.2mA   -30.39mA
-880mV    -41.78mA   -117.2mA   -15.62mA
-870mV    -30.28mA   -100.2mA   -12.04mA
-840mV    -13.1mA    -50.87mA   -7.186mA
-810mV    -7.18mA    -24.07mA   -5.432mA
-780mV    -4.86mA    -12.37mA   -4.416mA
-700mV    -2.552mA   -3.603mA   -2.454mA
-350mV    -11.93uA   -60.06uA   -2.46uA
6.6V      10.25nA    1.32uA     122.8pA
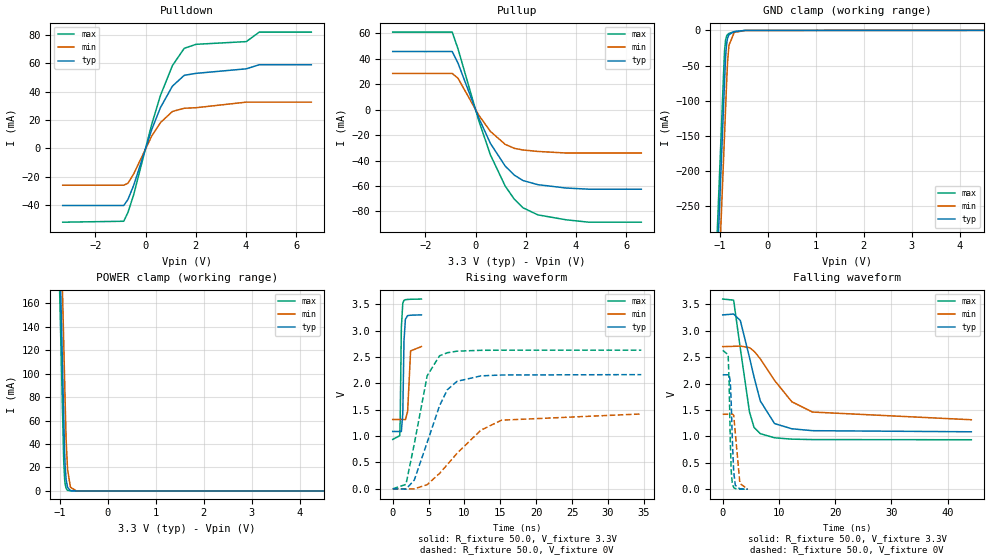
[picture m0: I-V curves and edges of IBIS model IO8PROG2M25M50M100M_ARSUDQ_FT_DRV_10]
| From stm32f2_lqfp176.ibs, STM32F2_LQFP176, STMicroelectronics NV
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| *** New cell (Generated with 5.14beta1 (Sep 20 2010 13:23:23))
[Model]   IO8PROG2M25M50M100M_ARSUDQ_FT_DRV_10
Model_type 3-state
Polarity   Non-Inverting
Enable   Active-Low
| CAP_THRESHOLD on pad IOV33 is "CMOS" :
| Rising=10.0% of vddio   Falling=90.0% of vddio
| C_comp min and max val. don't necessarily correlate with the min and max pvt
| but are the smallest and greatest pad capacitance found.
| var   typ   min   max
C_comp   2.14325pF  2.03775pF  2.26775pF
Vmeas = 1.65V   | Reference voltage for timing measurements
Cref  = 50.0pF   | Timing specification test load capacitance value
Rref  = 10.0MOhm   | Timing specification test load resistance value
Vref  = 1.65V   | Timing specification test load voltage
[Model Spec]
| variable   typ   min   max
[Temperature Range] 25.0 125.0 -40.0
| variable   typ   min   max
[Voltage Range] 3.3V 2.7V 3.6V
| variable   typ   min   max
[POWER Clamp Reference] 3.3V 2.7V 3.6V
| variable   typ   min   max
[GND Clamp Reference] 0V 0V 0V
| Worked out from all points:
|   slope of the pulldown table from 0 to 0.495 V, typ, clamps not added: 20 ohm
|   slope of the pullup table from 0 to 0.495 V, typ, clamps not added: 21.7 ohm
|   GND clamp passes 1 mA (typ) near -0.62 V on its own axis
|   POWER clamp passes 1 mA (typ) near -0.81 V on its own axis
|   rising waveform, R_fixture 50.0, V_fixture 3.3V: 20-80 % time 162ps typ, 212ps min, 146ps max; typ from 1.09 V to 3.3 V
|   falling waveform, R_fixture 50.0, V_fixture 3.3V: 20-80 % time 3.16ns typ, 6.11ns min, 2.07ns max; typ from 3.3 V to 1.09 V
|   rising waveform, R_fixture 50.0, V_fixture 0V: 20-80 % time 3.26ns typ, 6.07ns min, 2.16ns max; typ from 0 V to 2.17 V
|   falling waveform, R_fixture 50.0, V_fixture 0V: 20-80 % time 416ps typ, 600ps min, 330ps max; typ from 2.17 V to 0.001 V
[POWER Clamp]
-3.3V     4.11A      4.173A     4.072A
-1.09V    352.5mA    415.9mA    314.5mA
-1.05V    284.5mA    347.9mA    246.5mA
-1.01V    216.5mA    279.9mA    178.5mA
-920mV    63.51mA    126.9mA    25.85mA
-900mV    31.51mA    92.9mA     9.552mA
-890mV    21.35mA    75.9mA     5.807mA
-870mV    9.804mA    44.01mA    2.146mA
-840mV    3.05mA     18.36mA    482.1uA
-780mV    295.2uA    3.194mA    24.34uA
-660mV    2.764uA    96.54uA    62.42nA
6.6V      0A         0A         0A
[GND Clamp]
-3.3V     -4.149A    -4.223A    -4.103A
-1.06V    -340.6mA   -415.4mA   -294.5mA
-940mV    -136.6mA   -211.4mA   -90.54mA
-910mV    -85.55mA   -160.4mA   -39.54mA
-900mV    -68.55mA   -143.4mA   -26.55mA
-880mV    -36.73mA   -109.4mA   -13.46mA
-860mV    -19.54mA   -75.4mA    -8.234mA
-840mV    -11.29mA   -44.89mA   -5.954mA
-810mV    -6.008mA   -21.13mA   -4.401mA
-700mV    -1.958mA   -2.906mA   -1.882mA
-470mV    -105.5uA   -263.9uA   -47.31uA
6.6V      9.456nA    1.185uA    63.86pA
| variable   typ   min   max
[Pullup Reference] 3.3V 2.7V 3.6V
| variable   typ   min   max
[Pulldown Reference] 0V 0V 0V
[Pullup]
-3.3V     45.78mA    28.54mA    61.09mA
-930mV    45.78mA    28.54mA    61.09mA
-700mV    36.69mA    24.76mA    47.9mA
120mV     -6.142mA   -4.065mA   -8.189mA
590mV     -26.5mA    -17.07mA   -35.52mA
1.18V     -44.36mA   -27.27mA   -60.11mA
1.54V     -51.43mA   -30.39mA   -70.35mA
1.89V     -55.75mA   -31.69mA   -77.18mA
2.48V     -58.98mA   -32.83mA   -82.75mA
3.6V      -61.62mA   -34.07mA   -86.61mA
4.51V     -62.54mA   -34.07mA   -88.51mA
6.6V      -62.54mA   -34.07mA   -88.51mA
[Pulldown]
-3.3V     -40.26mA   -25.94mA   -51.99mA
-870mV    -40.25mA   -25.94mA   -51.33mA
-700mV    -35.92mA   -24.51mA   -45.06mA
-470mV    -25.89mA   -17.87mA   -32.39mA
240mV     12.97mA    8.52mA     16.62mA
590mV     28.62mA    18.11mA    37.2mA
1.07V     43.85mA    26mA       58.31mA
1.54V     51.42mA    28.24mA    70.48mA
2.01V     52.82mA    28.63mA    73.27mA
4.01V     56.01mA    32.56mA    75.18mA
4.53V     58.89mA    32.56mA    81.88mA
6.6V      58.89mA    32.56mA    81.88mA
[Ramp]
dV/dt_r 1.29886V/3.25885ns 851.30598mV/6.06766ns 1.57728V/2.15568ns
dV/dt_f 1.32782V/3.15688ns 831.60155mV/6.1212ns 1.59819V/2.06848ns
R_load = 50.0
| Removed startup time: 0s 0s 0s  .
| Removed end time: 3.999ns.
[Rising Waveform]
R_fixture   = 50.0
V_fixture   = 3.3V
V_fixture_min = 2.7V
V_fixture_max = 3.6V
0s        1.087V     1.314V     936.3mV
981ps     1.087V     1.314V     1.007V
1.043ns   1.086V     1.314V     1.292V
1.204ns   1.086V     1.314V     3.055V
1.407ns   1.433V     1.314V     3.523V
1.571ns   2.8V       1.313V     3.573V
1.766ns   3.215V     1.309V     3.586V
2.082ns   3.285V     1.467V     3.591V
2.493ns   3.292V     2.615V     3.594V
4.001ns   3.298V     2.697V     3.598V
| Removed startup time: 0s 0s 0s  .
| Removed end time: 44.195ns.
[Falling Waveform]
R_fixture   = 50.0
V_fixture   = 3.3V
V_fixture_min = 2.7V
V_fixture_max = 3.6V
0s        3.3V       2.7V       3.6V
1.94ns    3.316V     2.705V     3.58V
3.135ns   3.193V     2.71V      2.663V
4.755ns   2.497V     2.68V      1.465V
5.575ns   2.121V     2.613V     1.169V
6.685ns   1.671V     2.469V     1.051V
9.215ns   1.243V     2.06V      973.1mV
12.29ns   1.144V     1.655V     947.7mV
15.95ns   1.108V     1.461V     939.7mV
44.2ns    1.087V     1.315V     936.3mV
| Removed startup time: 0s 0s 0s  .
| Removed end time: 34.64ns.
[Rising Waveform]
R_fixture   = 50.0
V_fixture   = 0V
V_fixture_min = 0V
V_fixture_max = 0V
0s        7.746nV    280.7nV    5.708nV
1.845ns   -7.567mV   -1.837mV   82.52mV
3.005ns   164.5mV    -1.722mV   848.4mV
4.805ns   879.7mV    77.74mV    2.143V
6.53ns    1.575V     291.5mV    2.523V
7.61ns    1.878V     457.9mV    2.58V
8.985ns   2.039V     676mV      2.61V
12.29ns   2.141V     1.111V     2.626V
15.17ns   2.158V     1.301V     2.628V
34.65ns   2.165V     1.419V     2.629V
| Removed startup time: 0s 0s 0s  .
| Removed end time: 4.427ns.
[Falling Waveform]
R_fixture   = 50.0
V_fixture   = 0V
V_fixture_min = 0V
V_fixture_max = 0V
0s        2.165V     1.419V     2.629V
967ps     2.166V     1.419V     2.545V
1.142ns   2.171V     1.419V     2.016V
1.357ns   2.025V     1.418V     883.8mV
1.517ns   1.622V     1.42V      340.7mV
1.704ns   956.7mV    1.425V     109.9mV
1.954ns   331.2mV    1.4V       31.13mV
2.245ns   73.29mV    1.059V     11.16mV
3.057ns   5.65mV     107.7mV    2.134mV
4.429ns   973.2uV    1.887mV    613.1uV
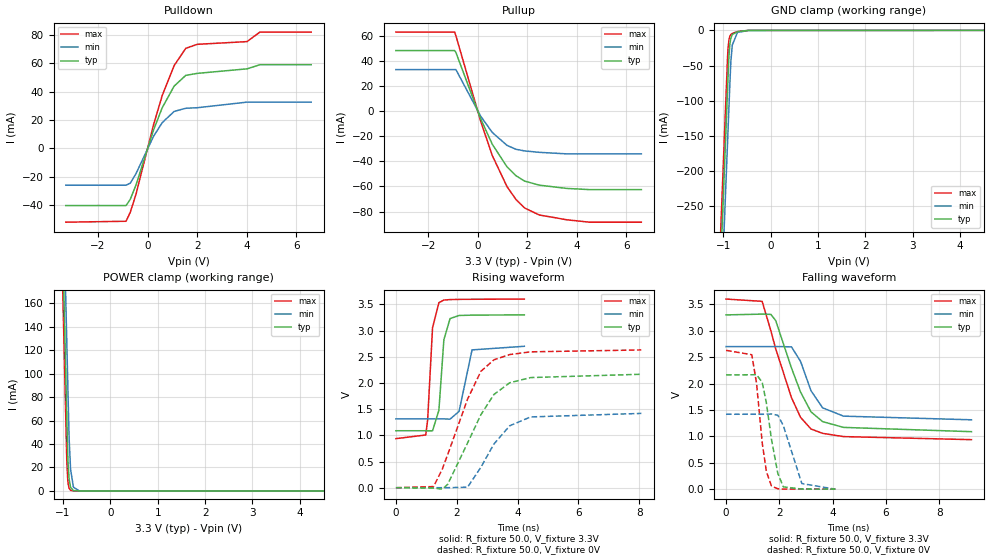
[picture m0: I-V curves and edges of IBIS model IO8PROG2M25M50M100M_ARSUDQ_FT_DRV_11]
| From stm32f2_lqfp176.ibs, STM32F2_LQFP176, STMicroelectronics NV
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| *** New cell (Generated with 5.14beta1 (Sep 20 2010 13:23:23))
[Model]   IO8PROG2M25M50M100M_ARSUDQ_FT_DRV_11
Model_type 3-state
Polarity   Non-Inverting
Enable   Active-Low
| CAP_THRESHOLD on pad IOV33 is "CMOS" :
| Rising=10.0% of vddio   Falling=90.0% of vddio
| C_comp min and max val. don't necessarily correlate with the min and max pvt
| but are the smallest and greatest pad capacitance found.
| var   typ   min   max
C_comp   2.14325pF  2.03775pF  2.26775pF
Vmeas = 1.65V   | Reference voltage for timing measurements
Cref  = 50.0pF   | Timing specification test load capacitance value
Rref  = 10.0MOhm   | Timing specification test load resistance value
Vref  = 1.65V   | Timing specification test load voltage
[Model Spec]
| variable   typ   min   max
[Temperature Range] 25.0 125.0 -40.0
| variable   typ   min   max
[Voltage Range] 3.3V 2.7V 3.6V
| variable   typ   min   max
[POWER Clamp Reference] 3.3V 2.7V 3.6V
| variable   typ   min   max
[GND Clamp Reference] 0V 0V 0V
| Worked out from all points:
|   slope of the pulldown table from 0 to 0.495 V, typ, clamps not added: 20 ohm
|   slope of the pullup table from 0 to 0.495 V, typ, clamps not added: 21.7 ohm
|   GND clamp passes 1 mA (typ) near -0.62 V on its own axis
|   POWER clamp passes 1 mA (typ) near -0.81 V on its own axis
|   rising waveform, R_fixture 50.0, V_fixture 3.3V: 20-80 % time 164ps typ, 213ps min, 147ps max; typ from 1.09 V to 3.3 V
|   falling waveform, R_fixture 50.0, V_fixture 3.3V: 20-80 % time 1.01ns typ, 720ps min, 1.03ns max; typ from 3.3 V to 1.09 V
|   rising waveform, R_fixture 50.0, V_fixture 0V: 20-80 % time 1.11ns typ, 947ps min, 1.03ns max; typ from 0 V to 2.17 V
|   falling waveform, R_fixture 50.0, V_fixture 0V: 20-80 % time 398ps typ, 473ps min, 327ps max; typ from 2.17 V to 0 V
[POWER Clamp]
-3.3V     4.11A      4.173A     4.072A
-1.09V    352.5mA    415.9mA    314.5mA
-1.05V    284.5mA    347.9mA    246.5mA
-1.01V    216.5mA    279.9mA    178.5mA
-920mV    63.51mA    126.9mA    25.85mA
-900mV    31.51mA    92.9mA     9.552mA
-890mV    21.35mA    75.9mA     5.807mA
-870mV    9.804mA    44.01mA    2.146mA
-840mV    3.05mA     18.36mA    482.1uA
-780mV    295.2uA    3.194mA    24.34uA
-660mV    2.764uA    96.54uA    62.42nA
6.6V      0A         0A         0A
[GND Clamp]
-3.3V     -4.149A    -4.223A    -4.103A
-1.06V    -340.6mA   -415.4mA   -294.5mA
-940mV    -136.6mA   -211.4mA   -90.54mA
-910mV    -85.55mA   -160.4mA   -39.54mA
-900mV    -68.55mA   -143.4mA   -26.55mA
-880mV    -36.73mA   -109.4mA   -13.46mA
-860mV    -19.54mA   -75.4mA    -8.234mA
-840mV    -11.29mA   -44.89mA   -5.954mA
-810mV    -6.008mA   -21.13mA   -4.401mA
-700mV    -1.958mA   -2.906mA   -1.882mA
-470mV    -105.5uA   -263.9uA   -47.31uA
6.6V      9.456nA    1.185uA    63.86pA
| variable   typ   min   max
[Pullup Reference] 3.3V 2.7V 3.6V
| variable   typ   min   max
[Pulldown Reference] 0V 0V 0V
[Pullup]
-3.3V     48.28mA    33.1mA     63mA
-930mV    48.28mA    33.1mA     63mA
-880mV    46.73mA    33.1mA     60.07mA
120mV     -6.142mA   -4.065mA   -8.189mA
590mV     -26.5mA    -17.07mA   -35.52mA
1.18V     -44.36mA   -27.27mA   -60.11mA
1.54V     -51.43mA   -30.39mA   -70.35mA
1.89V     -55.75mA   -31.69mA   -77.18mA
2.48V     -58.98mA   -32.83mA   -82.75mA
3.6V      -61.62mA   -34.07mA   -86.61mA
4.51V     -62.54mA   -34.07mA   -88.51mA
6.6V      -62.54mA   -34.07mA   -88.51mA
[Pulldown]
-3.3V     -40.26mA   -25.94mA   -51.99mA
-870mV    -40.25mA   -25.94mA   -51.33mA
-700mV    -35.92mA   -24.51mA   -45.06mA
-470mV    -25.89mA   -17.87mA   -32.39mA
240mV     12.97mA    8.52mA     16.62mA
590mV     28.62mA    18.11mA    37.2mA
1.07V     43.85mA    26mA       58.31mA
1.54V     51.42mA    28.24mA    70.48mA
2.01V     52.82mA    28.63mA    73.27mA
4.01V     56.01mA    32.56mA    75.18mA
4.53V     58.89mA    32.56mA    81.88mA
6.6V      58.89mA    32.56mA    81.88mA
[Ramp]
dV/dt_r 1.29886V/1.11419ns 851.3068mV/947.95689ps 1.57773V/1.03382ns
dV/dt_f 1.32806V/1.00883ns 831.60271mV/720.92084ps 1.59819V/1.03423ns
R_load = 50.0
| Removed startup time: 0s 0s 0s  .
| Removed end time: 4.219ns.
[Rising Waveform]
R_fixture   = 50.0
V_fixture   = 3.3V
V_fixture_min = 2.7V
V_fixture_max = 3.6V
0s        1.087V     1.314V     936.3mV
981ps     1.087V     1.314V     1.006V
1.043ns   1.086V     1.314V     1.296V
1.204ns   1.086V     1.314V     3.052V
1.413ns   1.478V     1.314V     3.532V
1.576ns   2.823V     1.313V     3.581V
1.78ns    3.228V     1.309V     3.59V
2.076ns   3.287V     1.457V     3.594V
2.502ns   3.293V     2.63V      3.596V
4.221ns   3.299V     2.699V     3.6V
| Removed startup time: 0s 0s 0s  .
| Removed end time: 9.202ns.
[Falling Waveform]
R_fixture   = 50.0
V_fixture   = 3.3V
V_fixture_min = 2.7V
V_fixture_max = 3.6V
0s        3.3V       2.7V       3.6V
1.353ns   3.315V     2.7V       3.557V
1.681ns   3.31V      2.7V       2.998V
1.862ns   3.193V     2.702V     2.659V
2.453ns   2.295V     2.695V     1.734V
2.794ns   1.839V     2.42V      1.36V
3.185ns   1.465V     1.865V     1.14V
3.622ns   1.279V     1.54V      1.057V
4.406ns   1.17V      1.383V     995.8mV
9.204ns   1.089V     1.314V     937.9mV
| Removed startup time: 0s 0s 0s  .
| Removed end time: 8.066ns.
[Rising Waveform]
R_fixture   = 50.0
V_fixture   = 0V
V_fixture_min = 0V
V_fixture_max = 0V
0s        7.762nV    280.7nV    5.723nV
1.238ns   -6.373mV   5.065uV    21.86mV
1.524ns   -27.8mV    112.5uV    353.8mV
1.702ns   64.33mV    295.9uV    631.6mV
2.355ns   853.6mV    9.934mV    1.69V
2.793ns   1.393V     389.7mV    2.221V
3.22ns    1.778V     832.8mV    2.44V
3.743ns   2.003V     1.183V     2.541V
4.429ns   2.102V     1.351V     2.593V
8.068ns   2.165V     1.418V     2.629V
| Removed startup time: 0s 0s 0s  .
| Removed end time: 4.097ns.
[Falling Waveform]
R_fixture   = 50.0
V_fixture   = 0V
V_fixture_min = 0V
V_fixture_max = 0V
0s        2.165V     1.419V     2.629V
966ps     2.166V     1.419V     2.546V
1.142ns   2.17V      1.419V     2.014V
1.357ns   2.022V     1.418V     875.8mV
1.513ns   1.633V     1.42V      335mV
1.702ns   948.9mV    1.424V     61.38mV
1.942ns   297.5mV    1.4V       7.26mV
2.15ns    44.36mV    1.201V     3.055mV
2.843ns   2.357mV    106.3mV    1.307mV
4.099ns   482.6uV    511.1uV    396.7uV
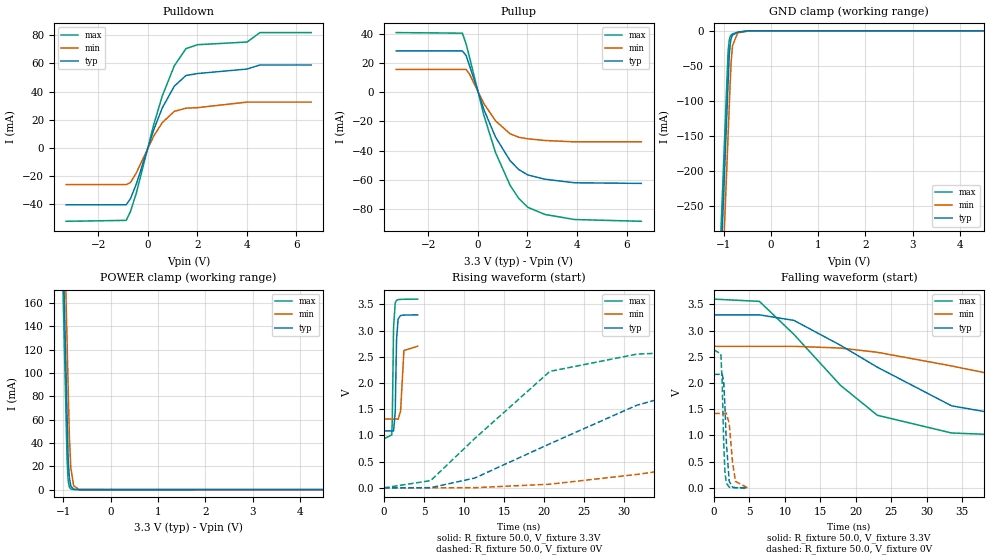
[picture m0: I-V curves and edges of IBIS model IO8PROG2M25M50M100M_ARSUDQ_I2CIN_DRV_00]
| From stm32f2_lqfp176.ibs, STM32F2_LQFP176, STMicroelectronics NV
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| *** New cell (Generated with 5.14beta1 (Sep 20 2010 13:23:23))
[Model]   IO8PROG2M25M50M100M_ARSUDQ_I2CIN_DRV_00
Model_type 3-state
Polarity   Non-Inverting
Enable   Active-Low
| CAP_THRESHOLD on pad IOV33 is "CMOS" :
| Rising=10.0% of vddio   Falling=90.0% of vddio
| C_comp min and max val. don't necessarily correlate with the min and max pvt
| but are the smallest and greatest pad capacitance found.
| var   typ   min   max
C_comp   2.14165pF  2.03605pF  2.26615pF
Vmeas = 1.65V   | Reference voltage for timing measurements
Cref  = 50.0pF   | Timing specification test load capacitance value
Rref  = 10.0MOhm   | Timing specification test load resistance value
Vref  = 1.65V   | Timing specification test load voltage
[Model Spec]
| variable   typ   min   max
[Temperature Range] 25.0 125.0 -40.0
| variable   typ   min   max
[Voltage Range] 3.3V 2.7V 3.6V
| variable   typ   min   max
[POWER Clamp Reference] 3.3V 2.7V 3.6V
| variable   typ   min   max
[GND Clamp Reference] 0V 0V 0V
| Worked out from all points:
|   slope of the pulldown table from 0 to 0.495 V, typ, clamps not added: 20 ohm
|   slope of the pullup table from 0 to 0.495 V, typ, clamps not added: 21.7 ohm
|   GND clamp passes 1 mA (typ) near -0.62 V on its own axis
|   POWER clamp passes 1 mA (typ) near -0.81 V on its own axis
|   rising waveform, R_fixture 50.0, V_fixture 3.3V: 20-80 % time 162ps typ, 212ps min, 145ps max; typ from 1.09 V to 3.3 V
|   falling waveform, R_fixture 50.0, V_fixture 3.3V: 20-80 % time 18.1ns typ, 35.5ns min, 11.7ns max; typ from 3.3 V to 1.09 V
|   rising waveform, R_fixture 50.0, V_fixture 0V: 20-80 % time 19.4ns typ, 44ns min, 10.8ns max; typ from 0 V to 2.17 V
|   falling waveform, R_fixture 50.0, V_fixture 0V: 20-80 % time 416ps typ, 600ps min, 329ps max; typ from 2.17 V to 0 V
[POWER Clamp]
-3.3V     4.11A      4.173A     4.072A
-1.09V    352.5mA    415.9mA    314.5mA
-1.05V    284.5mA    347.9mA    246.5mA
-1.01V    216.5mA    279.9mA    178.5mA
-920mV    63.51mA    126.9mA    25.85mA
-900mV    31.51mA    92.9mA     9.552mA
-890mV    21.35mA    75.9mA     5.807mA
-870mV    9.804mA    44.01mA    2.146mA
-840mV    3.05mA     18.36mA    482.1uA
-780mV    295.2uA    3.194mA    24.34uA
-660mV    2.764uA    96.54uA    62.42nA
6.6V      0A         0A         0A
[GND Clamp]
-3.3V     -4.149A    -4.223A    -4.103A
-1.06V    -340.6mA   -415.4mA   -294.5mA
-940mV    -136.6mA   -211.4mA   -90.54mA
-910mV    -85.55mA   -160.4mA   -39.54mA
-900mV    -68.55mA   -143.4mA   -26.55mA
-880mV    -36.73mA   -109.4mA   -13.46mA
-860mV    -19.54mA   -75.4mA    -8.234mA
-840mV    -11.29mA   -44.89mA   -5.954mA
-810mV    -6.008mA   -21.13mA   -4.401mA
-700mV    -1.958mA   -2.906mA   -1.882mA
-470mV    -105.5uA   -263.9uA   -47.31uA
6.6V      9.456nA    1.185uA    63.86pA
| variable   typ   min   max
[Pullup Reference] 3.3V 2.7V 3.6V
| variable   typ   min   max
[Pulldown Reference] 0V 0V 0V
[Pullup]
-3.3V     28.27mA    15.58mA    40.81mA
-630mV    28.27mA    15.58mA    40.39mA
-480mV    25.11mA    15.58mA    33.22mA
-350mV    18.69mA    12.64mA    24.51mA
240mV     -11.89mA   -7.822mA   -15.87mA
710mV     -30.8mA    -19.68mA   -41.36mA
1.3V      -47.02mA   -28.56mA   -63.9mA
1.65V     -53.05mA   -30.92mA   -72.82mA
2.01V     -56.71mA   -31.98mA   -78.86mA
2.7V      -59.67mA   -33.14mA   -83.8mA
3.9V      -62.11mA   -34.07mA   -87.29mA
6.6V      -62.54mA   -34.07mA   -88.51mA
[Pulldown]
-3.3V     -40.26mA   -25.94mA   -51.99mA
-870mV    -40.25mA   -25.94mA   -51.33mA
-700mV    -35.92mA   -24.51mA   -45.06mA
-470mV    -25.89mA   -17.87mA   -32.39mA
240mV     12.97mA    8.52mA     16.62mA
590mV     28.62mA    18.11mA    37.2mA
1.07V     43.85mA    26mA       58.31mA
1.54V     51.42mA    28.24mA    70.48mA
2.01V     52.82mA    28.63mA    73.27mA
4.01V     56.01mA    32.56mA    75.18mA
4.53V     58.89mA    32.56mA    81.88mA
6.6V      58.89mA    32.56mA    81.88mA
[Ramp]
dV/dt_r 1.29886V/19.42097ns 851.12033mV/43.99577ns 1.57728V/10.78197ns
dV/dt_f 1.3278V/18.11042ns 831.26708mV/35.47264ns 1.59819V/11.72029ns
R_load = 50.0
| Removed startup time: 0s 0s 0s  .
| Removed end time: 4.206ns.
[Rising Waveform]
R_fixture   = 50.0
V_fixture   = 3.3V
V_fixture_min = 2.7V
V_fixture_max = 3.6V
0s        1.087V     1.314V     936.3mV
980ps     1.087V     1.314V     1.01V
1.042ns   1.086V     1.314V     1.299V
1.202ns   1.086V     1.314V     3.057V
1.406ns   1.442V     1.314V     3.527V
1.572ns   2.819V     1.313V     3.577V
1.77ns    3.222V     1.308V     3.59V
2.076ns   3.287V     1.463V     3.594V
2.494ns   3.295V     2.619V     3.596V
4.21ns    3.299V     2.7V       3.599V
| Removed startup time: 0s 0s 0s  .
| Removed end time: 252.0ns.
[Falling Waveform]
R_fixture   = 50.0
V_fixture   = 3.3V
V_fixture_min = 2.7V
V_fixture_max = 3.6V
0s        3.3V       2.7V       3.6V
6.4ns     3.3V       2.7V       3.557V
11.28ns   3.194V     2.7V       2.926V
17.84ns   2.72V      2.667V     1.956V
23.04ns   2.302V     2.586V     1.385V
33.52ns   1.565V     2.326V     1.047V
47.92ns   1.226V     1.929V     972mV
63.8ns    1.144V     1.611V     948.7mV
84.68ns   1.108V     1.446V     940mV
252.1ns   1.087V     1.315V     936.3mV
| Removed startup time: 0s 0s 0s  .
| Removed end time: 243.84ns.
[Rising Waveform]
R_fixture   = 50.0
V_fixture   = 0V
V_fixture_min = 0V
V_fixture_max = 0V
0s        7.742nV    280.7nV    5.714nV
5.84ns    3.463mV    -133.1uV   138.7mV
11.36ns   188.2mV    3.445mV    944mV
20.72ns   840.7mV    69.51mV    2.221V
31.6ns    1.577V     256.2mV    2.551V
39.4ns    1.904V     422.9mV    2.599V
49ns      2.053V     639.3mV    2.619V
72.56ns   2.144V     1.079V     2.628V
94.44ns   2.16V      1.285V     2.629V
243.9ns   2.165V     1.419V     2.629V
| Removed startup time: 0s 0s 0s  .
| Removed end time: 4.754ns.
[Falling Waveform]
R_fixture   = 50.0
V_fixture   = 0V
V_fixture_min = 0V
V_fixture_max = 0V
0s        2.165V     1.419V     2.629V
958ps     2.166V     1.419V     2.558V
1.14ns    2.172V     1.419V     2.02V
1.352ns   2.031V     1.418V     901.5mV
1.524ns   1.593V     1.42V      322.4mV
1.722ns   896.4mV    1.426V     96.78mV
2.132ns   126mV      1.231V     13.57mV
2.606ns   14.65mV    489.2mV    3.217mV
3.022ns   4.255mV    123.1mV    1.983mV
4.758ns   438.1uV    308.7uV    610.7uV
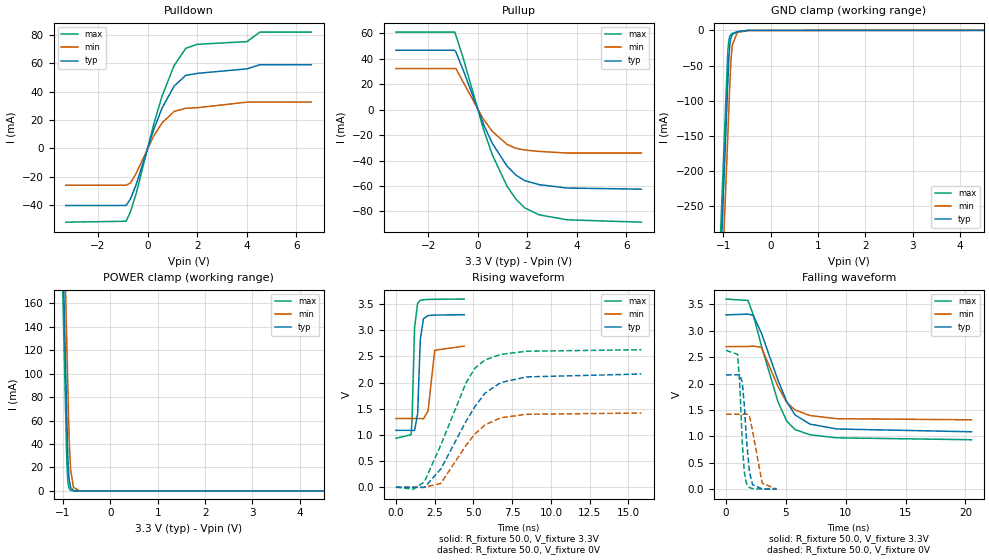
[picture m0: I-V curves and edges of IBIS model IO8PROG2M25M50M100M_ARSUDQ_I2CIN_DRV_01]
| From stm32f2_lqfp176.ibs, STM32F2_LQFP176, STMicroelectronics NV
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| *** New cell (Generated with 5.14beta1 (Sep 20 2010 13:23:23))
[Model]   IO8PROG2M25M50M100M_ARSUDQ_I2CIN_DRV_01
Model_type 3-state
Polarity   Non-Inverting
Enable   Active-Low
| CAP_THRESHOLD on pad IOV33 is "CMOS" :
| Rising=10.0% of vddio   Falling=90.0% of vddio
| C_comp min and max val. don't necessarily correlate with the min and max pvt
| but are the smallest and greatest pad capacitance found.
| var   typ   min   max
C_comp   2.14165pF  2.03605pF  2.26615pF
Vmeas = 1.65V   | Reference voltage for timing measurements
Cref  = 50.0pF   | Timing specification test load capacitance value
Rref  = 10.0MOhm   | Timing specification test load resistance value
Vref  = 1.65V   | Timing specification test load voltage
[Model Spec]
| variable   typ   min   max
[Temperature Range] 25.0 125.0 -40.0
| variable   typ   min   max
[Voltage Range] 3.3V 2.7V 3.6V
| variable   typ   min   max
[POWER Clamp Reference] 3.3V 2.7V 3.6V
| variable   typ   min   max
[GND Clamp Reference] 0V 0V 0V
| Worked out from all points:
|   slope of the pulldown table from 0 to 0.495 V, typ, clamps not added: 20 ohm
|   slope of the pullup table from 0 to 0.495 V, typ, clamps not added: 21.7 ohm
|   GND clamp passes 1 mA (typ) near -0.62 V on its own axis
|   POWER clamp passes 1 mA (typ) near -0.81 V on its own axis
|   rising waveform, R_fixture 50.0, V_fixture 3.3V: 20-80 % time 162ps typ, 213ps min, 146ps max; typ from 1.09 V to 3.3 V
|   falling waveform, R_fixture 50.0, V_fixture 3.3V: 20-80 % time 2.27ns typ, 1.77ns min, 2.11ns max; typ from 3.3 V to 1.09 V
|   rising waveform, R_fixture 50.0, V_fixture 0V: 20-80 % time 2.49ns typ, 2.07ns min, 2.19ns max; typ from 0 V to 2.17 V
|   falling waveform, R_fixture 50.0, V_fixture 0V: 20-80 % time 416ps typ, 599ps min, 330ps max; typ from 2.17 V to 0.001 V
[POWER Clamp]
-3.3V     4.11A      4.173A     4.072A
-1.09V    352.5mA    415.9mA    314.5mA
-1.05V    284.5mA    347.9mA    246.5mA
-1.01V    216.5mA    279.9mA    178.5mA
-920mV    63.51mA    126.9mA    25.85mA
-900mV    31.51mA    92.9mA     9.552mA
-890mV    21.35mA    75.9mA     5.807mA
-870mV    9.804mA    44.01mA    2.146mA
-840mV    3.05mA     18.36mA    482.1uA
-780mV    295.2uA    3.194mA    24.34uA
-660mV    2.764uA    96.54uA    62.42nA
6.6V      0A         0A         0A
[GND Clamp]
-3.3V     -4.149A    -4.223A    -4.103A
-1.06V    -340.6mA   -415.4mA   -294.5mA
-940mV    -136.6mA   -211.4mA   -90.54mA
-910mV    -85.55mA   -160.4mA   -39.54mA
-900mV    -68.55mA   -143.4mA   -26.55mA
-880mV    -36.73mA   -109.4mA   -13.46mA
-860mV    -19.54mA   -75.4mA    -8.234mA
-840mV    -11.29mA   -44.89mA   -5.954mA
-810mV    -6.008mA   -21.13mA   -4.401mA
-700mV    -1.958mA   -2.906mA   -1.882mA
-470mV    -105.5uA   -263.9uA   -47.31uA
6.6V      9.456nA    1.185uA    63.86pA
| variable   typ   min   max
[Pullup Reference] 3.3V 2.7V 3.6V
| variable   typ   min   max
[Pulldown Reference] 0V 0V 0V
[Pullup]
-3.3V     46.81mA    32.38mA    61.09mA
-930mV    46.81mA    32.38mA    61.09mA
-880mV    45.47mA    32.38mA    58.55mA
-590mV    31.39mA    21.85mA    40.84mA
240mV     -11.89mA   -7.822mA   -15.87mA
590mV     -26.5mA    -17.07mA   -35.52mA
1.18V     -44.36mA   -27.27mA   -60.11mA
1.54V     -51.43mA   -30.39mA   -70.35mA
1.89V     -55.75mA   -31.69mA   -77.18mA
2.48V     -58.98mA   -32.83mA   -82.75mA
3.6V      -61.62mA   -34.07mA   -86.61mA
6.6V      -62.54mA   -34.07mA   -88.51mA
[Pulldown]
-3.3V     -40.26mA   -25.94mA   -51.99mA
-870mV    -40.25mA   -25.94mA   -51.33mA
-700mV    -35.92mA   -24.51mA   -45.06mA
-470mV    -25.89mA   -17.87mA   -32.39mA
240mV     12.97mA    8.52mA     16.62mA
590mV     28.62mA    18.11mA    37.2mA
1.07V     43.85mA    26mA       58.31mA
1.54V     51.42mA    28.24mA    70.48mA
2.01V     52.82mA    28.63mA    73.27mA
4.01V     56.01mA    32.56mA    75.18mA
4.53V     58.89mA    32.56mA    81.88mA
6.6V      58.89mA    32.56mA    81.88mA
[Ramp]
dV/dt_r 1.29886V/2.49189ns 851.30661mV/2.07175ns 1.57728V/2.18764ns
dV/dt_f 1.32782V/2.26572ns 831.60249mV/1.76793ns 1.59819V/2.10954ns
R_load = 50.0
| Removed startup time: 0s 0s 0s  .
| Removed end time: 4.401ns.
[Rising Waveform]
R_fixture   = 50.0
V_fixture   = 3.3V
V_fixture_min = 2.7V
V_fixture_max = 3.6V
0s        1.087V     1.314V     936.3mV
977ps     1.087V     1.314V     1.004V
1.042ns   1.086V     1.314V     1.302V
1.2ns     1.086V     1.314V     3.044V
1.399ns   1.402V     1.314V     3.519V
1.572ns   2.819V     1.313V     3.574V
1.774ns   3.221V     1.309V     3.586V
2.072ns   3.283V     1.457V     3.591V
2.502ns   3.292V     2.619V     3.594V
4.403ns   3.298V     2.698V     3.598V
| Removed startup time: 0s 0s 0s  .
| Removed end time: 20.485ns.
[Falling Waveform]
R_fixture   = 50.0
V_fixture   = 3.3V
V_fixture_min = 2.7V
V_fixture_max = 3.6V
0s        3.3V       2.7V       3.6V
1.835ns   3.315V     2.701V     3.574V
2.265ns   3.293V     2.711V     3.307V
2.95ns    2.957V     2.684V     2.718V
4.33ns    2.067V     1.948V     1.661V
5.065ns   1.661V     1.644V     1.29V
5.765ns   1.405V     1.501V     1.128V
7.015ns   1.232V     1.394V     1.031V
9.26ns    1.14V      1.335V     972.6mV
20.5ns    1.087V     1.314V     936.7mV
| Removed startup time: 0s 0s 0s  .
| Removed end time: 15.815ns.
[Rising Waveform]
R_fixture   = 50.0
V_fixture   = 0V
V_fixture_min = 0V
V_fixture_max = 0V
0s        7.767nV    280.7nV    5.727nV
1.14ns    -600.7uV   -6.691uV   -37.17mV
1.835ns   -3.779mV   -1.917mV   102.3mV
2.9ns     350.7mV    74.05mV    808.4mV
4.52ns    1.26V      800.2mV    1.997V
5.1ns     1.544V     1.019V     2.279V
5.745ns   1.799V     1.192V     2.434V
6.755ns   2.001V     1.328V     2.539V
8.435ns   2.11V      1.395V     2.601V
15.83ns   2.165V     1.419V     2.629V
| Removed startup time: 0s 0s 0s  .
| Removed end time: 4.232ns.
[Falling Waveform]
R_fixture   = 50.0
V_fixture   = 0V
V_fixture_min = 0V
V_fixture_max = 0V
0s        2.165V     1.419V     2.629V
960ps     2.166V     1.419V     2.554V
1.139ns   2.171V     1.419V     2.023V
1.355ns   2.024V     1.418V     886.7mV
1.516ns   1.619V     1.42V      340.1mV
1.705ns   947.2mV    1.425V     108.5mV
1.953ns   330.1mV    1.397V     31.19mV
2.212ns   85.88mV    1.105V     12.2mV
3.022ns   4.605mV    112.9mV    1.901mV
4.234ns   782.5uV    1.127mV    586.6uV
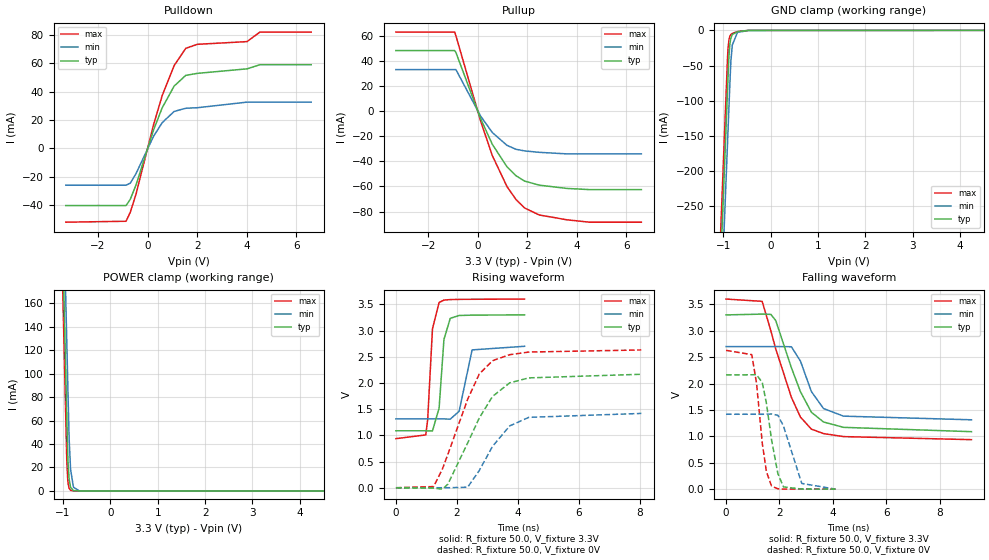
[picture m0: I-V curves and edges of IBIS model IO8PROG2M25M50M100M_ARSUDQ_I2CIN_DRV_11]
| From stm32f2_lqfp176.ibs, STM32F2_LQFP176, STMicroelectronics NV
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| *** New cell (Generated with 5.14beta1 (Sep 20 2010 13:23:23))
[Model]   IO8PROG2M25M50M100M_ARSUDQ_I2CIN_DRV_11
Model_type 3-state
Polarity   Non-Inverting
Enable   Active-Low
| CAP_THRESHOLD on pad IOV33 is "CMOS" :
| Rising=10.0% of vddio   Falling=90.0% of vddio
| C_comp min and max val. don't necessarily correlate with the min and max pvt
| but are the smallest and greatest pad capacitance found.
| var   typ   min   max
C_comp   2.14165pF  2.03605pF  2.26615pF
Vmeas = 1.65V   | Reference voltage for timing measurements
Cref  = 50.0pF   | Timing specification test load capacitance value
Rref  = 10.0MOhm   | Timing specification test load resistance value
Vref  = 1.65V   | Timing specification test load voltage
[Model Spec]
| variable   typ   min   max
[Temperature Range] 25.0 125.0 -40.0
| variable   typ   min   max
[Voltage Range] 3.3V 2.7V 3.6V
| variable   typ   min   max
[POWER Clamp Reference] 3.3V 2.7V 3.6V
| variable   typ   min   max
[GND Clamp Reference] 0V 0V 0V
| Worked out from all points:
|   slope of the pulldown table from 0 to 0.495 V, typ, clamps not added: 20 ohm
|   slope of the pullup table from 0 to 0.495 V, typ, clamps not added: 21.7 ohm
|   GND clamp passes 1 mA (typ) near -0.62 V on its own axis
|   POWER clamp passes 1 mA (typ) near -0.81 V on its own axis
|   rising waveform, R_fixture 50.0, V_fixture 3.3V: 20-80 % time 163ps typ, 213ps min, 147ps max; typ from 1.09 V to 3.3 V
|   falling waveform, R_fixture 50.0, V_fixture 3.3V: 20-80 % time 1.01ns typ, 720ps min, 1.03ns max; typ from 3.3 V to 1.09 V
|   rising waveform, R_fixture 50.0, V_fixture 0V: 20-80 % time 1.11ns typ, 947ps min, 1.03ns max; typ from 0 V to 2.17 V
|   falling waveform, R_fixture 50.0, V_fixture 0V: 20-80 % time 398ps typ, 473ps min, 327ps max; typ from 2.17 V to 0 V
[POWER Clamp]
-3.3V     4.11A      4.173A     4.072A
-1.09V    352.5mA    415.9mA    314.5mA
-1.05V    284.5mA    347.9mA    246.5mA
-1.01V    216.5mA    279.9mA    178.5mA
-920mV    63.51mA    126.9mA    25.85mA
-900mV    31.51mA    92.9mA     9.552mA
-890mV    21.35mA    75.9mA     5.807mA
-870mV    9.804mA    44.01mA    2.146mA
-840mV    3.05mA     18.36mA    482.1uA
-780mV    295.2uA    3.194mA    24.34uA
-660mV    2.764uA    96.54uA    62.42nA
6.6V      0A         0A         0A
[GND Clamp]
-3.3V     -4.149A    -4.223A    -4.103A
-1.06V    -340.6mA   -415.4mA   -294.5mA
-940mV    -136.6mA   -211.4mA   -90.54mA
-910mV    -85.55mA   -160.4mA   -39.54mA
-900mV    -68.55mA   -143.4mA   -26.55mA
-880mV    -36.73mA   -109.4mA   -13.46mA
-860mV    -19.54mA   -75.4mA    -8.234mA
-840mV    -11.29mA   -44.89mA   -5.954mA
-810mV    -6.008mA   -21.13mA   -4.401mA
-700mV    -1.958mA   -2.906mA   -1.882mA
-470mV    -105.5uA   -263.9uA   -47.31uA
6.6V      9.456nA    1.185uA    63.86pA
| variable   typ   min   max
[Pullup Reference] 3.3V 2.7V 3.6V
| variable   typ   min   max
[Pulldown Reference] 0V 0V 0V
[Pullup]
-3.3V     48.28mA    33.1mA     63mA
-930mV    48.28mA    33.1mA     63mA
-880mV    46.73mA    33.1mA     60.07mA
120mV     -6.142mA   -4.065mA   -8.189mA
590mV     -26.5mA    -17.07mA   -35.52mA
1.18V     -44.36mA   -27.27mA   -60.11mA
1.54V     -51.43mA   -30.39mA   -70.35mA
1.89V     -55.75mA   -31.69mA   -77.18mA
2.48V     -58.98mA   -32.83mA   -82.75mA
3.6V      -61.62mA   -34.07mA   -86.61mA
4.51V     -62.54mA   -34.07mA   -88.51mA
6.6V      -62.54mA   -34.07mA   -88.51mA
[Pulldown]
-3.3V     -40.26mA   -25.94mA   -51.99mA
-870mV    -40.25mA   -25.94mA   -51.33mA
-700mV    -35.92mA   -24.51mA   -45.06mA
-470mV    -25.89mA   -17.87mA   -32.39mA
240mV     12.97mA    8.52mA     16.62mA
590mV     28.62mA    18.11mA    37.2mA
1.07V     43.85mA    26mA       58.31mA
1.54V     51.42mA    28.24mA    70.48mA
2.01V     52.82mA    28.63mA    73.27mA
4.01V     56.01mA    32.56mA    75.18mA
4.53V     58.89mA    32.56mA    81.88mA
6.6V      58.89mA    32.56mA    81.88mA
[Ramp]
dV/dt_r 1.29886V/1.11461ns 851.3068mV/947.87496ps 1.57728V/1.0346ns
dV/dt_f 1.32771V/1.00908ns 831.60271mV/720.21307ps 1.59819V/1.03466ns
R_load = 50.0
| Removed startup time: 0s 0s 0s  .
| Removed end time: 4.217ns.
[Rising Waveform]
R_fixture   = 50.0
V_fixture   = 3.3V
V_fixture_min = 2.7V
V_fixture_max = 3.6V
0s        1.087V     1.314V     936.3mV
980ps     1.087V     1.314V     1.008V
1.042ns   1.086V     1.314V     1.304V
1.199ns   1.085V     1.314V     3.035V
1.416ns   1.519V     1.314V     3.535V
1.575ns   2.83V      1.313V     3.581V
1.782ns   3.232V     1.309V     3.59V
2.073ns   3.287V     1.459V     3.594V
2.498ns   3.293V     2.63V      3.596V
4.219ns   3.299V     2.699V     3.6V
| Removed startup time: 0s 0s 0s  .
| Removed end time: 9.191ns.
[Falling Waveform]
R_fixture   = 50.0
V_fixture   = 3.3V
V_fixture_min = 2.7V
V_fixture_max = 3.6V
0s        3.3V       2.7V       3.6V
1.352ns   3.315V     2.7V       3.557V
1.68ns    3.31V      2.7V       2.996V
1.862ns   3.192V     2.702V     2.656V
2.447ns   2.301V     2.697V     1.74V
2.786ns   1.847V     2.426V     1.366V
3.196ns   1.457V     1.849V     1.137V
3.651ns   1.272V     1.527V     1.053V
4.401ns   1.171V     1.383V     995.7mV
9.193ns   1.089V     1.314V     937.9mV
| Removed startup time: 0s 0s 0s  .
| Removed end time: 8.047ns.
[Rising Waveform]
R_fixture   = 50.0
V_fixture   = 0V
V_fixture_min = 0V
V_fixture_max = 0V
0s        7.76nV     280.7nV    5.707nV
1.237ns   -6.511mV   5.691uV    22.63mV
1.522ns   -27.17mV   115.2uV    353.9mV
1.702ns   66.56mV    280uV      634.8mV
2.352ns   853.3mV    10.24mV    1.688V
2.733ns   1.33V      327.9mV    2.169V
3.169ns   1.743V     790.2mV    2.424V
3.732ns   2.001V     1.18V      2.539V
4.358ns   2.096V     1.343V     2.589V
8.049ns   2.165V     1.418V     2.629V
| Removed startup time: 0s 0s 0s  .
| Removed end time: 4.097ns.
[Falling Waveform]
R_fixture   = 50.0
V_fixture   = 0V
V_fixture_min = 0V
V_fixture_max = 0V
0s        2.165V     1.419V     2.629V
964ps     2.166V     1.419V     2.547V
1.141ns   2.17V      1.419V     2.012V
1.358ns   2.017V     1.418V     865.5mV
1.514ns   1.624V     1.42V      329.6mV
1.705ns   933.5mV    1.424V     58.45mV
1.942ns   294mV      1.399V     7.21mV
2.15ns    43.66mV    1.197V     3.04mV
2.836ns   2.375mV    109.1mV    1.314mV
4.099ns   481.4uV    504.2uV    397.6uV
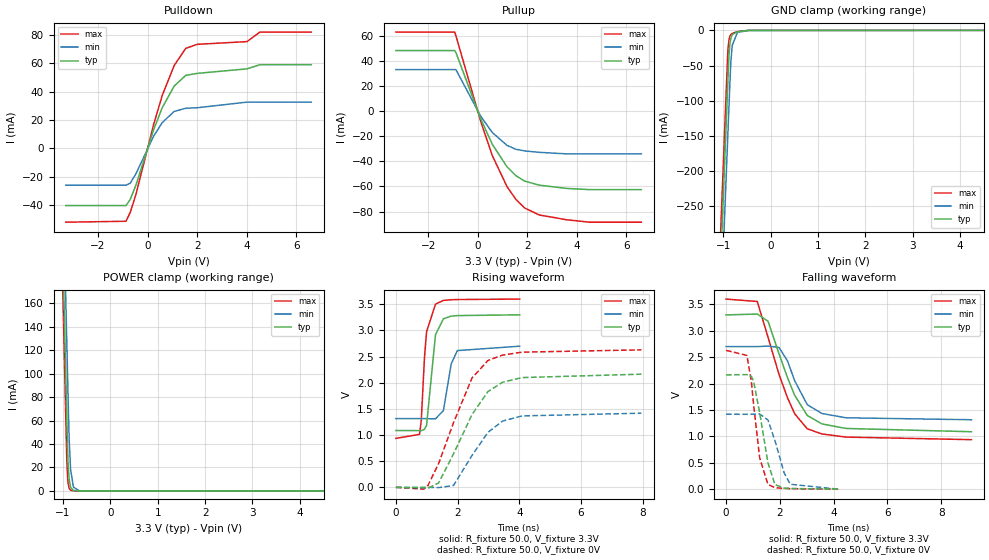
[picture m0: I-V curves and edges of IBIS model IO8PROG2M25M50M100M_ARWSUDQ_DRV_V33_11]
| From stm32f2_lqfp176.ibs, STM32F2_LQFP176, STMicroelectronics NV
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| *** New cell (Generated with 5.14beta1 (Sep 20 2010 13:23:23))
[Model]   IO8PROG2M25M50M100M_ARWSUDQ_DRV_V33_11
Model_type 3-state
Polarity   Non-Inverting
Enable   Active-Low
| CAP_THRESHOLD on pad IOV33 is "CMOS" :
| Rising=10.0% of vddio   Falling=90.0% of vddio
| C_comp min and max val. don't necessarily correlate with the min and max pvt
| but are the smallest and greatest pad capacitance found.
| var   typ   min   max
C_comp   2.45680pF  2.35635pF  2.58870pF
Vmeas = 1.65V   | Reference voltage for timing measurements
Cref  = 50.0pF   | Timing specification test load capacitance value
Rref  = 1.0MOhm   | Timing specification test load resistance value
Vref  = 1.65V   | Timing specification test load voltage
[Model Spec]
| variable   typ   min   max
[Temperature Range] 25.0 125.0 -40.0
| variable   typ   min   max
[Voltage Range] 3.3V 2.7V 3.6V
| variable   typ   min   max
[POWER Clamp Reference] 3.3V 2.7V 3.6V
| variable   typ   min   max
[GND Clamp Reference] 0V 0V 0V
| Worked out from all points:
|   slope of the pulldown table from 0 to 0.495 V, typ, clamps not added: 20 ohm
|   slope of the pullup table from 0 to 0.495 V, typ, clamps not added: 21.7 ohm
|   GND clamp passes 1 mA (typ) near -0.62 V on its own axis
|   POWER clamp passes 1 mA (typ) near -0.81 V on its own axis
|   rising waveform, R_fixture 50.0, V_fixture 3.3V: 20-80 % time 188ps typ, 232ps min, 174ps max; typ from 1.09 V to 3.3 V
|   falling waveform, R_fixture 50.0, V_fixture 3.3V: 20-80 % time 1.03ns typ, 746ps min, 1.05ns max; typ from 3.3 V to 1.09 V
|   rising waveform, R_fixture 50.0, V_fixture 0V: 20-80 % time 1.13ns typ, 962ps min, 1.05ns max; typ from 0 V to 2.16 V
|   falling waveform, R_fixture 50.0, V_fixture 0V: 20-80 % time 417ps typ, 487ps min, 349ps max; typ from 2.17 V to 0.001 V
[POWER Clamp]
-3.3V     4.11A      4.173A     4.072A
-1.09V    352.6mA    415.9mA    314.7mA
-1.05V    284.6mA    347.9mA    246.7mA
-1.01V    216.6mA    279.9mA    178.7mA
-920mV    63.6mA     126.9mA    25.98mA
-900mV    31.61mA    92.95mA    9.679mA
-890mV    21.44mA    75.95mA    5.93mA
-870mV    9.888mA    44.06mA    2.262mA
-840mV    3.126mA    18.4mA     586.7uA
-780mV    356.4uA    3.233mA    107.9uA
-660mV    37.87uA    120.8uA    47.09uA
6.6V      0A         0A         0A
[GND Clamp]
-3.3V     -4.149A    -4.224A    -4.103A
-1.06V    -340.8mA   -415.7mA   -294.7mA
-940mV    -136.8mA   -211.7mA   -90.7mA
-910mV    -85.75mA   -160.7mA   -39.7mA
-900mV    -68.75mA   -143.7mA   -26.69mA
-880mV    -36.92mA   -109.7mA   -13.58mA
-860mV    -19.7mA    -75.66mA   -8.314mA
-840mV    -11.43mA   -45.13mA   -6.003mA
-810mV    -6.09mA    -21.34mA   -4.418mA
-700mV    -1.961mA   -2.954mA   -1.882mA
-470mV    -105.5uA   -264uA     -47.31uA
6.6V      9.775nA    1.217uA    66.58pA
| variable   typ   min   max
[Pullup Reference] 3.3V 2.7V 3.6V
| variable   typ   min   max
[Pulldown Reference] 0V 0V 0V
[Pullup]
-3.3V     48.29mA    33.1mA     63.02mA
-930mV    48.29mA    33.1mA     63.02mA
-880mV    46.74mA    33.1mA     60.09mA
120mV     -6.142mA   -4.065mA   -8.189mA
590mV     -26.5mA    -17.07mA   -35.52mA
1.18V     -44.36mA   -27.27mA   -60.11mA
1.54V     -51.43mA   -30.39mA   -70.35mA
1.89V     -55.75mA   -31.69mA   -77.18mA
2.48V     -58.98mA   -32.83mA   -82.75mA
3.6V      -61.62mA   -34.07mA   -86.61mA
4.51V     -62.54mA   -34.07mA   -88.51mA
6.6V      -62.54mA   -34.07mA   -88.51mA
[Pulldown]
-3.3V     -40.26mA   -25.94mA   -51.99mA
-870mV    -40.25mA   -25.94mA   -51.33mA
-700mV    -35.92mA   -24.51mA   -45.06mA
-470mV    -25.89mA   -17.87mA   -32.39mA
240mV     12.97mA    8.52mA     16.62mA
590mV     28.62mA    18.11mA    37.2mA
1.07V     43.85mA    26mA       58.31mA
1.54V     51.42mA    28.24mA    70.48mA
2.01V     52.82mA    28.63mA    73.27mA
4.01V     56.01mA    32.56mA    75.18mA
4.53V     58.9mA     32.56mA    81.88mA
6.6V      58.9mA     32.56mA    81.88mA
[Ramp]
dV/dt_r 1.29886V/1.12674ns 851.3068mV/962.47515ps 1.57728V/1.0486ns
dV/dt_f 1.32782V/1.03228ns 831.60267mV/746.34288ps 1.59819V/1.05092ns
R_load = 50.0
| Removed startup time: 0s 0s 0s  .
| Removed end time: 4.01ns.
[Rising Waveform]
R_fixture   = 50.0
V_fixture   = 3.3V
V_fixture_min = 2.7V
V_fixture_max = 3.6V
0s        1.087V     1.314V     936.3mV
765ps     1.085V     1.314V     1.014V
822ps     1.084V     1.314V     1.283V
926ps     1.109V     1.314V     2.487V
993ps     1.185V     1.313V     2.973V
1.283ns   2.92V      1.311V     3.504V
1.539ns   3.223V     1.467V     3.574V
1.793ns   3.274V     2.361V     3.587V
1.99ns    3.284V     2.615V     3.591V
4.012ns   3.299V     2.699V     3.6V
| Removed startup time: 0s 0s 0s  .
| Removed end time: 9.121ns.
[Falling Waveform]
R_fixture   = 50.0
V_fixture   = 3.3V
V_fixture_min = 2.7V
V_fixture_max = 3.6V
0s        3.3V       2.7V       3.6V
1.16ns    3.316V     2.7V       3.554V
1.56ns    3.181V     2.71V      2.878V
1.971ns   2.561V     2.682V     2.17V
2.285ns   2.11V      2.427V     1.73V
2.55ns    1.779V     2.055V     1.429V
3.019ns   1.396V     1.6V       1.143V
3.565ns   1.236V     1.433V     1.046V
4.459ns   1.15V      1.352V     986.6mV
9.123ns   1.088V     1.315V     937.8mV
| Removed startup time: 0s 0s 0s  .
| Removed end time: 7.953ns.
[Rising Waveform]
R_fixture   = 50.0
V_fixture   = 0V
V_fixture_min = 0V
V_fixture_max = 0V
0s        11.77nV    319.6nV    8.622nV
902ps     -7.198mV   65.05uV    -34.6mV
1.04ns    -16.76mV   188uV      37.47mV
1.384ns   84.46mV    -5.374mV   455.2mV
1.869ns   643.6mV    37.25mV    1.24V
2.466ns   1.391V     609.8mV    2.09V
2.981ns   1.83V      1.05V      2.425V
3.455ns   2.01V      1.267V     2.529V
4.088ns   2.099V     1.366V     2.585V
7.955ns   2.164V     1.418V     2.629V
| Removed startup time: 0s 0s 0s  .
| Removed end time: 4.166ns.
[Falling Waveform]
R_fixture   = 50.0
V_fixture   = 0V
V_fixture_min = 0V
V_fixture_max = 0V
0s        2.165V     1.419V     2.629V
776ps     2.17V      1.418V     2.533V
941ps     2.137V     1.419V     2.037V
1.021ns   2.049V     1.42V      1.617V
1.25ns    1.45V      1.425V     593.1mV
1.557ns   498.6mV    1.311V     89.73mV
1.821ns   85.19mV    914mV      28.44mV
2.16ns    21.41mV    308.2mV    14.27mV
2.387ns   13.17mV    93.47mV    10.36mV
4.168ns   832.9uV    930.8uV    614.8uV
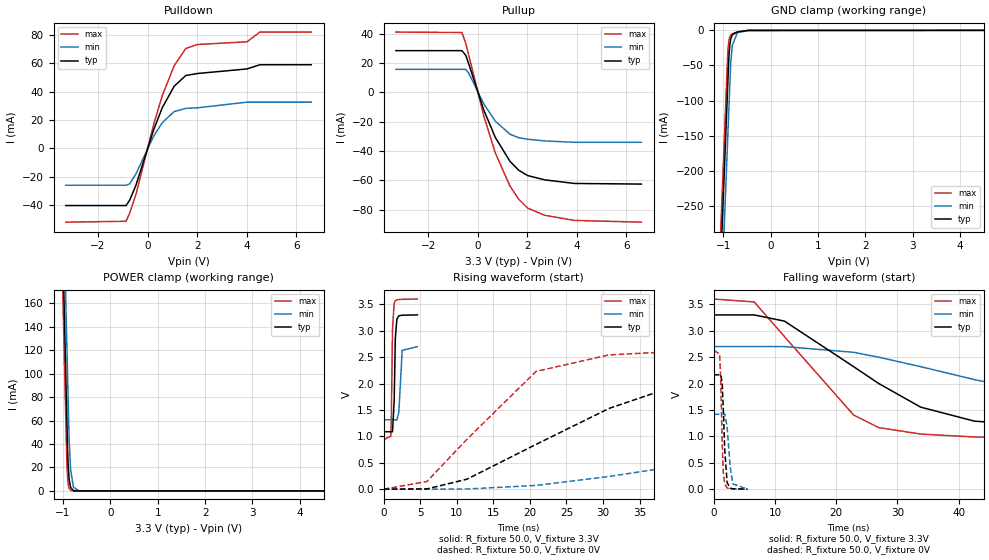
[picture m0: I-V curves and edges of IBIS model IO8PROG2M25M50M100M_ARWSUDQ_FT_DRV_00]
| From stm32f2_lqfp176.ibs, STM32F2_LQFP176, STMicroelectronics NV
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| *** New cell (Generated with 5.14beta1 (Sep 20 2010 13:23:23))
[Model]   IO8PROG2M25M50M100M_ARWSUDQ_FT_DRV_00
Model_type 3-state
Polarity   Non-Inverting
Enable   Active-Low
| CAP_THRESHOLD on pad IOV33 is "CMOS" :
| Rising=10.0% of vddio   Falling=90.0% of vddio
| C_comp min and max val. don't necessarily correlate with the min and max pvt
| but are the smallest and greatest pad capacitance found.
| var   typ   min   max
C_comp   2.32810pF  2.21810pF  2.46460pF
Vmeas = 1.65V   | Reference voltage for timing measurements
Cref  = 50.0pF   | Timing specification test load capacitance value
Rref  = 10.0MOhm   | Timing specification test load resistance value
Vref  = 1.65V   | Timing specification test load voltage
[Model Spec]
| variable   typ   min   max
[Temperature Range] 25.0 125.0 -40.0
| variable   typ   min   max
[Voltage Range] 3.3V 2.7V 3.6V
| variable   typ   min   max
[POWER Clamp Reference] 3.3V 2.7V 3.6V
| variable   typ   min   max
[GND Clamp Reference] 0V 0V 0V
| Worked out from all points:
|   slope of the pulldown table from 0 to 0.495 V, typ, clamps not added: 20 ohm
|   slope of the pullup table from 0 to 0.495 V, typ, clamps not added: 21.7 ohm
|   GND clamp passes 1 mA (typ) near -0.61 V on its own axis
|   POWER clamp passes 1 mA (typ) near -0.81 V on its own axis
|   rising waveform, R_fixture 50.0, V_fixture 3.3V: 20-80 % time 173ps typ, 218ps min, 159ps max; typ from 1.09 V to 3.3 V
|   falling waveform, R_fixture 50.0, V_fixture 3.3V: 20-80 % time 18.1ns typ, 35.5ns min, 11.7ns max; typ from 3.3 V to 1.09 V
|   rising waveform, R_fixture 50.0, V_fixture 0V: 20-80 % time 19.4ns typ, 44.1ns min, 10.8ns max; typ from 0 V to 2.17 V
|   falling waveform, R_fixture 50.0, V_fixture 0V: 20-80 % time 429ps typ, 612ps min, 343ps max; typ from 2.17 V to 0.001 V
[POWER Clamp]
-3.3V     4.11A      4.173A     4.072A
-1.09V    352.5mA    415.9mA    314.5mA
-1.05V    284.5mA    347.9mA    246.5mA
-1.01V    216.5mA    279.9mA    178.5mA
-920mV    63.51mA    126.9mA    25.85mA
-900mV    31.51mA    92.9mA     9.552mA
-890mV    21.35mA    75.9mA     5.807mA
-870mV    9.804mA    44.01mA    2.146mA
-840mV    3.05mA     18.36mA    482.1uA
-780mV    295.2uA    3.194mA    24.34uA
-660mV    2.764uA    96.52uA    62.42nA
6.6V      0A         0A         0A
[GND Clamp]
-3.3V     -4.149A    -4.224A    -4.103A
-1.06V    -341mA     -415.8mA   -295.1mA
-940mV    -137mA     -211.8mA   -91.11mA
-910mV    -86.01mA   -160.8mA   -40.11mA
-900mV    -69.01mA   -143.8mA   -27.13mA
-880mV    -37.2mA    -109.8mA   -14.07mA
-860mV    -20.02mA   -75.82mA   -8.837mA
-840mV    -11.77mA   -45.3mA    -6.542mA
-810mV    -6.468mA   -21.54mA   -4.94mA
-700mV    -2.247mA   -3.206mA   -2.168mA
-470mV    -130uA     -313.8uA   -60.76uA
6.6V      10.47nA    1.304uA    84.25pA
| variable   typ   min   max
[Pullup Reference] 3.3V 2.7V 3.6V
| variable   typ   min   max
[Pulldown Reference] 0V 0V 0V
[Pullup]
-3.3V     28.38mA    15.62mA    41.02mA
-640mV    28.38mA    15.62mA    40.74mA
-480mV    25.12mA    15.62mA    33.23mA
-350mV    18.69mA    12.65mA    24.51mA
240mV     -11.89mA   -7.822mA   -15.87mA
710mV     -30.8mA    -19.68mA   -41.36mA
1.3V      -47.02mA   -28.56mA   -63.9mA
1.65V     -53.05mA   -30.92mA   -72.82mA
2.01V     -56.71mA   -31.98mA   -78.86mA
2.7V      -59.67mA   -33.14mA   -83.8mA
3.9V      -62.11mA   -34.07mA   -87.29mA
6.6V      -62.54mA   -34.07mA   -88.51mA
[Pulldown]
-3.3V     -40.26mA   -25.94mA   -51.99mA
-870mV    -40.25mA   -25.94mA   -51.33mA
-720mV    -36.35mA   -24.93mA   -45.5mA
-470mV    -25.89mA   -17.87mA   -32.39mA
240mV     12.97mA    8.52mA     16.62mA
590mV     28.62mA    18.11mA    37.2mA
1.07V     43.85mA    26mA       58.31mA
1.54V     51.42mA    28.24mA    70.48mA
2.01V     52.82mA    28.63mA    73.27mA
4.01V     56.05mA    32.64mA    75.18mA
4.53V     59mA       32.64mA    82.02mA
6.6V      59mA       32.64mA    82.02mA
[Ramp]
dV/dt_r 1.29886V/19.41847ns 851.09629mV/44.08731ns 1.57728V/10.78438ns
dV/dt_f 1.3278V/18.1284ns 831.27468mV/35.4632ns 1.59819V/11.72248ns
R_load = 50.0
| Removed startup time: 0s 0s 0s  .
| Removed end time: 4.612ns.
[Rising Waveform]
R_fixture   = 50.0
V_fixture   = 3.3V
V_fixture_min = 2.7V
V_fixture_max = 3.6V
0s        1.087V     1.314V     936.3mV
978ps     1.087V     1.314V     1.003V
1.042ns   1.086V     1.314V     1.282V
1.212ns   1.087V     1.314V     3.024V
1.44ns    1.674V     1.314V     3.521V
1.594ns   2.852V     1.313V     3.569V
1.814ns   3.225V     1.309V     3.586V
2.082ns   3.282V     1.465V     3.591V
2.532ns   3.293V     2.627V     3.594V
4.616ns   3.299V     2.699V     3.599V
| Removed startup time: 0s 0s 0s  .
| Removed end time: 252.84ns.
[Falling Waveform]
R_fixture   = 50.0
V_fixture   = 3.3V
V_fixture_min = 2.7V
V_fixture_max = 3.6V
0s        3.3V       2.7V       3.6V
6.6ns     3.3V       2.7V       3.546V
11.56ns   3.182V     2.7V       2.888V
22.84ns   2.321V     2.592V     1.405V
26.92ns   2.003V     2.5V       1.167V
33.8ns    1.554V     2.32V      1.044V
42.6ns    1.288V     2.075V     988.4mV
59.08ns   1.16V      1.683V     953.1mV
85.04ns   1.108V     1.444V     939.9mV
252.9ns   1.087V     1.315V     936.3mV
| Removed startup time: 0s 0s 0s  .
| Removed end time: 245.0ns.
[Rising Waveform]
R_fixture   = 50.0
V_fixture   = 0V
V_fixture_min = 0V
V_fixture_max = 0V
0s        8.037nV    322.2nV    5.748nV
5.92ns    4.925mV    -130.9uV   144.9mV
11.4ns    188.9mV    2.93mV     946.4mV
20.84ns   847.2mV    70.4mV     2.229V
30.84ns   1.529V     240.1mV    2.542V
38.04ns   1.867V     391.8mV    2.593V
47.4ns    2.037V     602.2mV    2.616V
72.16ns   2.144V     1.072V     2.628V
97.08ns   2.16V      1.298V     2.629V
245.1ns   2.165V     1.418V     2.629V
| Removed startup time: 0s 0s 0s  .
| Removed end time: 5.51ns.
[Falling Waveform]
R_fixture   = 50.0
V_fixture   = 0V
V_fixture_min = 0V
V_fixture_max = 0V
0s        2.165V     1.419V     2.629V
962ps     2.166V     1.419V     2.557V
1.142ns   2.172V     1.419V     2.037V
1.372ns   2.008V     1.418V     877.3mV
1.55ns    1.535V     1.42V      324.7mV
1.782ns   769.4mV    1.428V     100.9mV
2.178ns   126.3mV    1.181V     23.1mV
2.67ns    20.88mV    439.7mV    8.288mV
3.106ns   8.152mV    101.1mV    4.967mV
5.514ns   572.9uV    580.9uV    658.6uV
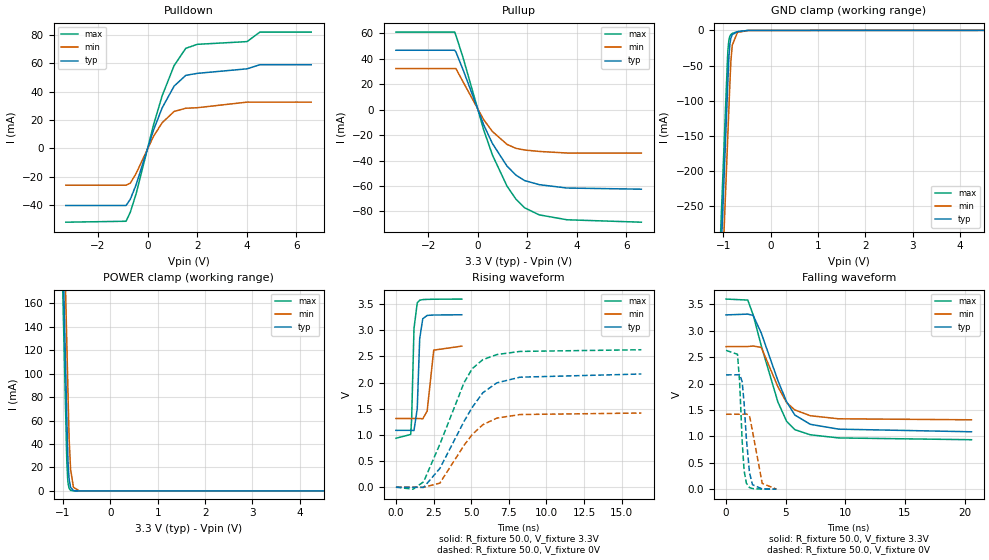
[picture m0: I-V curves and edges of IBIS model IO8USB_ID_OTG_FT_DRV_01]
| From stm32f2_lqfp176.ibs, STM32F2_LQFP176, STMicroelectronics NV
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| *** New cell (Generated with 5.14beta1 (Sep 20 2010 13:23:23))
[Model]   IO8USB_ID_OTG_FT_DRV_01
Model_type 3-state
Polarity   Non-Inverting
Enable   Active-Low
| CAP_THRESHOLD on pad IOV33 is "CMOS" :
| Rising=10.0% of vddio   Falling=90.0% of vddio
| C_comp min and max val. don't necessarily correlate with the min and max pvt
| but are the smallest and greatest pad capacitance found.
| var   typ   min   max
C_comp   2.14880pF  2.04280pF  2.27520pF
Vmeas = 1.65V   | Reference voltage for timing measurements
Cref  = 50.0pF   | Timing specification test load capacitance value
Rref  = 10.0MOhm   | Timing specification test load resistance value
Vref  = 1.65V   | Timing specification test load voltage
[Model Spec]
| variable   typ   min   max
[Temperature Range] 25.0 125.0 -40.0
| variable   typ   min   max
[Voltage Range] 3.3V 2.7V 3.6V
| variable   typ   min   max
[POWER Clamp Reference] 3.3V 2.7V 3.6V
| variable   typ   min   max
[GND Clamp Reference] 0V 0V 0V
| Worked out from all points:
|   slope of the pulldown table from 0 to 0.495 V, typ, clamps not added: 20 ohm
|   slope of the pullup table from 0 to 0.495 V, typ, clamps not added: 21.7 ohm
|   GND clamp passes 1 mA (typ) near -0.62 V on its own axis
|   POWER clamp passes 1 mA (typ) near -0.81 V on its own axis
|   rising waveform, R_fixture 50.0, V_fixture 3.3V: 20-80 % time 163ps typ, 213ps min, 146ps max; typ from 1.09 V to 3.3 V
|   falling waveform, R_fixture 50.0, V_fixture 3.3V: 20-80 % time 2.26ns typ, 1.77ns min, 2.11ns max; typ from 3.3 V to 1.09 V
|   rising waveform, R_fixture 50.0, V_fixture 0V: 20-80 % time 2.5ns typ, 2.08ns min, 2.19ns max; typ from 0 V to 2.17 V
|   falling waveform, R_fixture 50.0, V_fixture 0V: 20-80 % time 416ps typ, 600ps min, 331ps max; typ from 2.17 V to 0.001 V
[POWER Clamp]
-3.3V     4.11A      4.173A     4.072A
-1.09V    352.5mA    415.9mA    314.5mA
-1.05V    284.5mA    347.9mA    246.5mA
-1.01V    216.5mA    279.9mA    178.5mA
-920mV    63.51mA    126.9mA    25.85mA
-900mV    31.51mA    92.9mA     9.552mA
-890mV    21.35mA    75.9mA     5.807mA
-870mV    9.804mA    44.01mA    2.146mA
-840mV    3.05mA     18.36mA    482.1uA
-780mV    295.2uA    3.194mA    24.34uA
-660mV    2.764uA    96.54uA    62.42nA
6.6V      0A         0A         0A
[GND Clamp]
-3.3V     -4.149A    -4.223A    -4.103A
-1.06V    -340.6mA   -415.4mA   -294.6mA
-940mV    -136.6mA   -211.4mA   -90.55mA
-910mV    -85.56mA   -160.4mA   -39.55mA
-900mV    -68.56mA   -143.4mA   -26.56mA
-880mV    -36.74mA   -109.4mA   -13.48mA
-860mV    -19.55mA   -75.41mA   -8.247mA
-840mV    -11.31mA   -44.9mA    -5.968mA
-810mV    -6.021mA   -21.14mA   -4.415mA
-700mV    -1.968mA   -2.918mA   -1.891mA
-470mV    -106.7uA   -266.5uA   -47.83uA
6.6V      9.456nA    1.186uA    63.86pA
| variable   typ   min   max
[Pullup Reference] 3.3V 2.7V 3.6V
| variable   typ   min   max
[Pulldown Reference] 0V 0V 0V
[Pullup]
-3.3V     46.81mA    32.38mA    61.1mA
-930mV    46.81mA    32.38mA    61.1mA
-880mV    45.47mA    32.38mA    58.56mA
-590mV    31.4mA     21.86mA    40.84mA
240mV     -11.89mA   -7.822mA   -15.87mA
590mV     -26.5mA    -17.07mA   -35.52mA
1.18V     -44.36mA   -27.27mA   -60.11mA
1.54V     -51.43mA   -30.39mA   -70.35mA
1.89V     -55.75mA   -31.69mA   -77.18mA
2.48V     -58.98mA   -32.83mA   -82.75mA
3.6V      -61.62mA   -34.07mA   -86.61mA
6.6V      -62.54mA   -34.07mA   -88.51mA
[Pulldown]
-3.3V     -40.25mA   -25.94mA   -51.99mA
-870mV    -40.25mA   -25.94mA   -51.33mA
-700mV    -35.92mA   -24.51mA   -45.06mA
-470mV    -25.89mA   -17.87mA   -32.39mA
240mV     12.97mA    8.52mA     16.62mA
590mV     28.62mA    18.11mA    37.2mA
1.07V     43.85mA    26mA       58.31mA
1.54V     51.42mA    28.24mA    70.48mA
2.01V     52.82mA    28.63mA    73.27mA
4.01V     56.01mA    32.56mA    75.18mA
4.53V     58.9mA     32.56mA    81.88mA
6.6V      58.9mA     32.56mA    81.88mA
[Ramp]
dV/dt_r 1.29886V/2.49764ns 851.30661mV/2.07513ns 1.57728V/2.18604ns
dV/dt_f 1.32782V/2.26516ns 831.60249mV/1.76555ns 1.59819V/2.11089ns
R_load = 50.0
| Removed startup time: 0s 0s 0s  .
| Removed end time: 4.375ns.
[Rising Waveform]
R_fixture   = 50.0
V_fixture   = 3.3V
V_fixture_min = 2.7V
V_fixture_max = 3.6V
0s        1.087V     1.314V     936.3mV
982ps     1.087V     1.314V     1.009V
1.044ns   1.086V     1.314V     1.302V
1.201ns   1.085V     1.314V     3.036V
1.417ns   1.503V     1.314V     3.526V
1.579ns   2.837V     1.313V     3.576V
1.784ns   3.223V     1.309V     3.588V
2.076ns   3.285V     1.456V     3.592V
2.512ns   3.293V     2.621V     3.595V
4.377ns   3.298V     2.698V     3.598V
| Removed startup time: 0s 0s 0s  .
| Removed end time: 20.565ns.
[Falling Waveform]
R_fixture   = 50.0
V_fixture   = 3.3V
V_fixture_min = 2.7V
V_fixture_max = 3.6V
0s        3.3V       2.7V       3.6V
1.82ns    3.315V     2.701V     3.581V
2.275ns   3.29V      2.711V     3.3V
2.95ns    2.958V     2.685V     2.719V
4.345ns   2.058V     1.942V     1.652V
5.08ns    1.655V     1.639V     1.285V
5.775ns   1.403V     1.5V       1.127V
7.07ns    1.228V     1.391V     1.03V
9.44ns    1.137V     1.333V     970.7mV
20.58ns   1.087V     1.314V     936.6mV
| Removed startup time: 0s 0s 0s  .
| Removed end time: 16.3ns.
[Rising Waveform]
R_fixture   = 50.0
V_fixture   = 0V
V_fixture_min = 0V
V_fixture_max = 0V
0s        7.762nV    280.7nV    5.706nV
1.14ns    -486.8uV   -6.874uV   -37.21mV
1.84ns    -3.6mV     -1.933mV   103.5mV
2.92ns    359.6mV    78.63mV    822mV
4.53ns    1.261V     802.4mV    2V
5.07ns    1.526V     1.008V     2.267V
5.775ns   1.807V     1.195V     2.439V
6.71ns    1.996V     1.322V     2.537V
8.245ns   2.104V     1.39V      2.597V
16.31ns   2.165V     1.419V     2.629V
| Removed startup time: 0s 0s 0s  .
| Removed end time: 4.217ns.
[Falling Waveform]
R_fixture   = 50.0
V_fixture   = 0V
V_fixture_min = 0V
V_fixture_max = 0V
0s        2.165V     1.419V     2.629V
961ps     2.166V     1.419V     2.554V
1.14ns    2.171V     1.419V     2.024V
1.351ns   2.034V     1.418V     911.5mV
1.514ns   1.632V     1.42V      352.5mV
1.702ns   963mV      1.424V     115.3mV
1.965ns   314.6mV    1.393V     31.12mV
2.218ns   85.25mV    1.1V       11.66mV
3.031ns   4.035mV    110.1mV    1.492mV
4.219ns   647.2uV    947.8uV    493.7uV
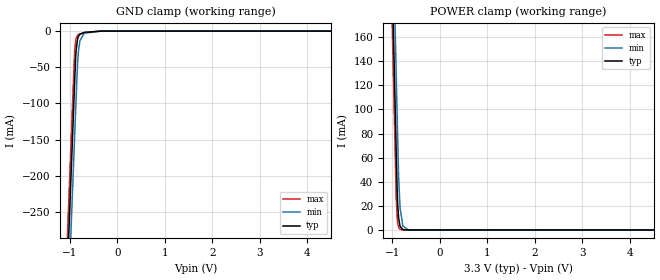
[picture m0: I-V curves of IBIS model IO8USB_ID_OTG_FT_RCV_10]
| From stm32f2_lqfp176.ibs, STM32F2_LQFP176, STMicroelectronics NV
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| *** New cell (Generated with 5.14beta1 (Sep 20 2010 13:23:23))
[Model]   IO8USB_ID_OTG_FT_RCV_10
Model_type Input
Polarity   Non-Inverting
Enable   Active-Low
| CAP_THRESHOLD on pad IOV33 is "CMOS" :
| Rising=10.0% of vddio   Falling=90.0% of vddio
| C_comp min and max val. don't necessarily correlate with the min and max pvt
| but are the smallest and greatest pad capacitance found.
| var   typ   min   max
C_comp   2.14545pF  2.04625pF  2.26745pF
Vinl = 810.0mV | Dummy value overriden by next lines
Vinh = 2.52V | Dummy value overriden by next lines
[Model Spec]
| TIME_THRESHOLD on pin ZIV12 is "CORE" :
| Rising=40.0% of vdd   Falling=60.0% of vdd
Vinl 1.48450V 1.23350V 1.61250V
Vinh 1.48450V 1.23350V 1.61250V
| variable   typ   min   max
[Temperature Range] 25.0 125.0 -40.0
| variable   typ   min   max
[Voltage Range] 3.3V 2.7V 3.6V
| variable   typ   min   max
[POWER Clamp Reference] 3.3V 2.7V 3.6V
| variable   typ   min   max
[GND Clamp Reference] 0V 0V 0V
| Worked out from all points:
|   GND clamp passes 1 mA (typ) near -0.62 V on its own axis
|   POWER clamp passes 1 mA (typ) near -0.81 V on its own axis
[POWER Clamp]
-3.3V     4.11A      4.173A     4.072A
-1.09V    352.5mA    415.9mA    314.5mA
-1.05V    284.5mA    347.9mA    246.5mA
-1.01V    216.5mA    279.9mA    178.5mA
-920mV    63.51mA    126.9mA    25.85mA
-900mV    31.51mA    92.9mA     9.552mA
-890mV    21.35mA    75.9mA     5.807mA
-870mV    9.804mA    44.01mA    2.146mA
-840mV    3.05mA     18.36mA    482.1uA
-780mV    295.2uA    3.194mA    24.34uA
-660mV    2.764uA    96.54uA    62.42nA
6.6V      0A         0A         0A
[GND Clamp]
-3.3V     -4.149A    -4.223A    -4.103A
-1.06V    -340.6mA   -415.4mA   -294.6mA
-940mV    -136.6mA   -211.4mA   -90.55mA
-900mV    -68.56mA   -143.4mA   -26.56mA
-880mV    -36.74mA   -109.4mA   -13.48mA
-870mV    -26.57mA   -92.41mA   -10.3mA
-840mV    -11.31mA   -44.9mA    -5.968mA
-820mV    -7.237mA   -26.99mA   -4.81mA
-790mV    -4.465mA   -13.32mA   -3.798mA
-700mV    -1.968mA   -2.918mA   -1.891mA
-350mV    -6.461uA   -36.64uA   -1.196uA
6.6V      9.456nA    1.186uA    63.86pA
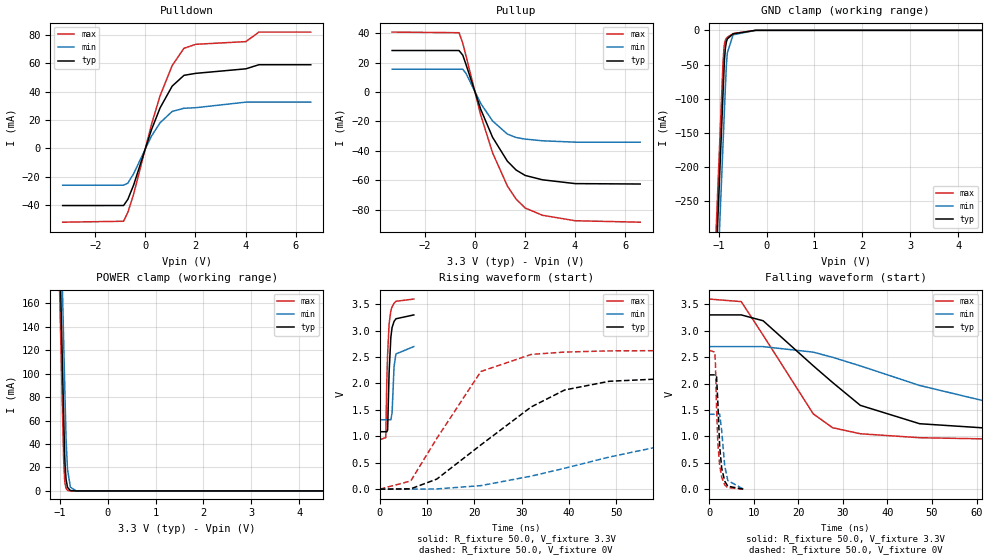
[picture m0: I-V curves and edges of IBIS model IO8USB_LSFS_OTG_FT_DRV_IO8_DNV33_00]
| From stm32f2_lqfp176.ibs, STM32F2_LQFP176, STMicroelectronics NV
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| *** New cell (Generated with 5.14beta1 (Sep 20 2010 13:23:23))
[Model]   IO8USB_LSFS_OTG_FT_DRV_IO8_DNV33_00
Model_type 3-state
Polarity   Non-Inverting
Enable   Active-Low
| CAP_THRESHOLD on pad DPV33 is "CMOS" :
| Rising=10.0% of vddio   Falling=90.0% of vddio
| C_comp min and max val. don't necessarily correlate with the min and max pvt
| but are the smallest and greatest pad capacitance found.
| var   typ   min   max
C_comp   5.85475pF  5.58530pF  6.39105pF
Vmeas = 1.65V   | Reference voltage for timing measurements
Cref  = 400.0pF   | Timing specification test load capacitance value
Rref  = 1.0MOhm   | Timing specification test load resistance value
Vref  = 1.65V   | Timing specification test load voltage
[Model Spec]
| variable   typ   min   max
[Temperature Range] 25.0 125.0 -40.0
| variable   typ   min   max
[Voltage Range] 3.3V 2.7V 3.6V
| variable   typ   min   max
[POWER Clamp Reference] 3.3V 2.7V 3.6V
| variable   typ   min   max
[GND Clamp Reference] 0V 0V 0V
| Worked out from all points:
|   slope of the pulldown table from 0 to 0.495 V, typ, clamps not added: 20 ohm
|   slope of the pullup table from 0 to 0.495 V, typ, clamps not added: 21.7 ohm
|   GND clamp passes 1 mA (typ) near -0.51 V on its own axis
|   POWER clamp passes 1 mA (typ) near -0.81 V on its own axis
|   rising waveform, R_fixture 50.0, V_fixture 3.3V: 20-80 % time 520ps typ, 457ps min, 535ps max; typ from 1.09 V to 3.3 V
|   falling waveform, R_fixture 50.0, V_fixture 3.3V: 20-80 % time 18.2ns typ, 35.5ns min, 11.8ns max; typ from 3.3 V to 1.09 V
|   rising waveform, R_fixture 50.0, V_fixture 0V: 20-80 % time 19.5ns typ, 44.2ns min, 10.8ns max; typ from 0 V to 2.17 V
|   falling waveform, R_fixture 50.0, V_fixture 0V: 20-80 % time 846ps typ, 985ps min, 766ps max; typ from 2.17 V to 0.001 V
[POWER Clamp]
-3.3V     4.11A      4.173A     4.072A
-1.09V    352.5mA    415.9mA    314.5mA
-1.05V    284.5mA    347.9mA    246.5mA
-1.01V    216.5mA    279.9mA    178.5mA
-920mV    63.51mA    126.9mA    25.85mA
-900mV    31.51mA    92.9mA     9.552mA
-890mV    21.35mA    75.9mA     5.807mA
-870mV    9.804mA    44.01mA    2.146mA
-840mV    3.05mA     18.36mA    482.1uA
-780mV    295.2uA    3.193mA    24.34uA
-660mV    2.775uA    96uA       63.85nA
6.6V      0A         0A         0A
[GND Clamp]
-3.3V     -4.155A    -4.23A     -4.11A
-1.06V    -347.4mA   -421.9mA   -301.9mA
-940mV    -143.4mA   -217.9mA   -97.86mA
-910mV    -92.43mA   -166.9mA   -46.86mA
-890mV    -58.43mA   -132.9mA   -25.36mA
-880mV    -43.4mA    -115.9mA   -20.1mA
-860mV    -25.79mA   -81.93mA   -14.41mA
-840mV    -17.12mA   -51.2mA    -11.69mA
-820mV    -12.64mA   -32.88mA   -10.09mA
-700mV    -5.102mA   -6.6mA     -4.73mA
-230mV    -826nA     -13.68uA   -47.8nA
6.6V      45.45nA    5.674uA    302.2pA
| variable   typ   min   max
[Pullup Reference] 3.3V 2.7V 3.6V
| variable   typ   min   max
[Pulldown Reference] 0V 0V 0V
[Pullup]
-3.3V     28.27mA    15.58mA    40.81mA
-630mV    28.27mA    15.58mA    40.39mA
-480mV    25.11mA    15.58mA    33.22mA
-350mV    18.69mA    12.64mA    24.51mA
240mV     -11.89mA   -7.822mA   -15.87mA
710mV     -30.8mA    -19.68mA   -41.36mA
1.3V      -47.02mA   -28.56mA   -63.9mA
1.65V     -53.05mA   -30.92mA   -72.82mA
2.01V     -56.71mA   -31.98mA   -78.86mA
2.7V      -59.67mA   -33.14mA   -83.8mA
4.01V     -62.27mA   -34.07mA   -87.53mA
6.6V      -62.54mA   -34.07mA   -88.51mA
[Pulldown]
-3.3V     -40.26mA   -25.94mA   -51.99mA
-870mV    -40.25mA   -25.94mA   -51.33mA
-700mV    -35.92mA   -24.51mA   -45.06mA
-470mV    -25.89mA   -17.87mA   -32.39mA
240mV     12.97mA    8.52mA     16.62mA
590mV     28.62mA    18.11mA    37.2mA
1.07V     43.85mA    26mA       58.31mA
1.54V     51.42mA    28.24mA    70.48mA
2.01V     52.82mA    28.63mA    73.27mA
4.01V     56.01mA    32.56mA    75.18mA
4.53V     58.89mA    32.56mA    81.88mA
6.6V      58.89mA    32.56mA    81.88mA
[Ramp]
dV/dt_r 1.29886V/19.48127ns 851.08826mV/44.21121ns 1.57727V/10.79614ns
dV/dt_f 1.3278V/18.1783ns 831.24622mV/35.48078ns 1.59819V/11.76231ns
R_load = 50.0
| Removed startup time: 0s 0s 0s  .
| Removed end time: 7.212ns.
[Rising Waveform]
R_fixture   = 50.0
V_fixture   = 3.3V
V_fixture_min = 2.7V
V_fixture_max = 3.6V
0s        1.087V     1.314V     936.3mV
1.292ns   1.087V     1.314V     975.4mV
1.492ns   1.085V     1.314V     2.018V
1.672ns   1.119V     1.314V     2.548V
1.984ns   2.202V     1.314V     3.124V
2.352ns   2.871V     1.312V     3.375V
2.616ns   3.06V      1.442V     3.45V
3.034ns   3.175V     2.319V     3.519V
3.436ns   3.225V     2.56V      3.556V
7.216ns   3.298V     2.698V     3.598V
| Removed startup time: 0s 0s 0s  .
| Removed end time: 252.2ns.
[Falling Waveform]
R_fixture   = 50.0
V_fixture   = 3.3V
V_fixture_min = 2.7V
V_fixture_max = 3.6V
0s        3.3V       2.7V       3.6V
7.2ns     3.3V       2.7V       3.552V
12.12ns   3.189V     2.7V       2.915V
23.36ns   2.337V     2.595V     1.427V
27.68ns   2.022V     2.498V     1.165V
33.92ns   1.588V     2.335V     1.05V
47.24ns   1.24V      1.964V     975.2mV
64.88ns   1.143V     1.608V     948.4mV
85.36ns   1.108V     1.446V     940mV
252.3ns   1.087V     1.315V     936.3mV
| Removed startup time: 0s 0s 0s  .
| Removed end time: 247.56ns.
[Rising Waveform]
R_fixture   = 50.0
V_fixture   = 0V
V_fixture_min = 0V
V_fixture_max = 0V
0s        17.02nV    1.21uV     10.94nV
6.56ns    6.322mV    -286.8uV   154.8mV
12.08ns   190.6mV    4.237mV    960.5mV
21.4ns    837.5mV    66.88mV    2.227V
32.04ns   1.556V     246.4mV    2.55V
39.12ns   1.877V     395.8mV    2.595V
48.56ns   2.042V     607.5mV    2.617V
73.36ns   2.144V     1.074V     2.628V
97.8ns    2.16V      1.298V     2.629V
247.6ns   2.165V     1.418V     2.629V
| Removed startup time: 0s 0s 0s  .
| Removed end time: 7.65ns.
[Falling Waveform]
R_fixture   = 50.0
V_fixture   = 0V
V_fixture_min = 0V
V_fixture_max = 0V
0s        2.165V     1.419V     2.629V
1.276ns   2.165V     1.419V     2.597V
1.406ns   2.167V     1.419V     2.386V
1.666ns   2.129V     1.419V     1.551V
1.94ns    1.671V     1.418V     888.8mV
2.364ns   807.6mV    1.424V     451.1mV
2.826ns   394.4mV    1.101V     226.5mV
3.496ns   152.5mV    437.5mV    80.36mV
4.19ns    57.34mV    165.2mV    30mV
7.654ns   1.324mV    3.119mV    1.184mV
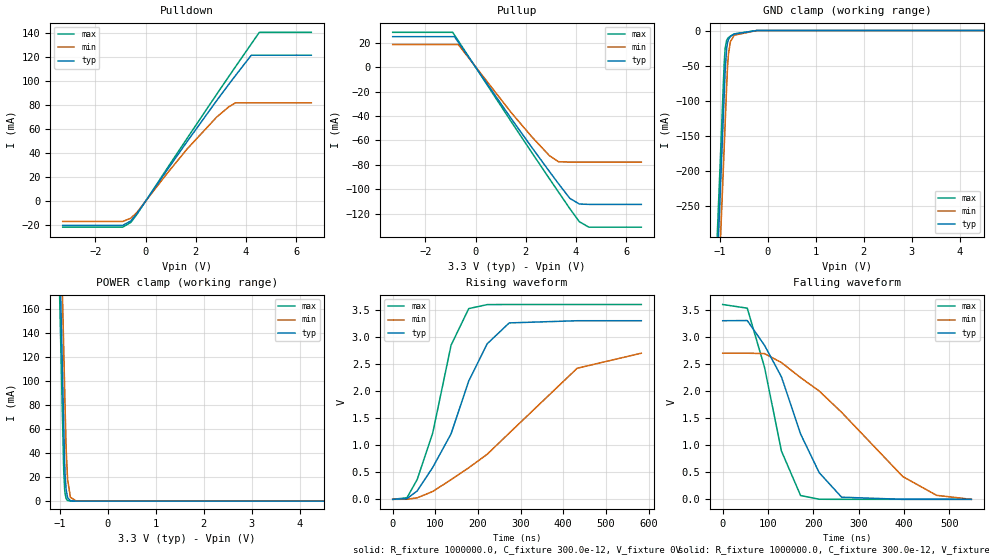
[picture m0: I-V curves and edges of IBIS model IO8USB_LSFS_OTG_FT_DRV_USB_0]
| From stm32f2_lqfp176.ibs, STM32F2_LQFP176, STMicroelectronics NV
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| *** New cell (Generated with 5.14beta1 (Sep 20 2010 13:23:23))
[Model]   IO8USB_LSFS_OTG_FT_DRV_USB_0
Model_type 3-state
Polarity   Non-Inverting
Enable   Active-Low
| CAP_THRESHOLD on pad DPV33 is "CMOS" :
| Rising=10.0% of vddio   Falling=90.0% of vddio
| C_comp min and max val. don't necessarily correlate with the min and max pvt
| but are the smallest and greatest pad capacitance found.
| var   typ   min   max
C_comp   5.85010pF  5.57930pF  6.38640pF
Vmeas = 1.65V   | Reference voltage for timing measurements
Cref  = 400.0pF   | Timing specification test load capacitance value
Rref  = 1.0MOhm   | Timing specification test load resistance value
Vref  = 1.65V   | Timing specification test load voltage
[Model Spec]
| variable   typ   min   max
[Temperature Range] 25.0 125.0 -40.0
| variable   typ   min   max
[Voltage Range] 3.3V 2.7V 3.6V
| variable   typ   min   max
[POWER Clamp Reference] 3.3V 2.7V 3.6V
| variable   typ   min   max
[GND Clamp Reference] 0V 0V 0V
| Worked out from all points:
|   slope of the pulldown table from 0 to 0.495 V, typ, clamps not added: 33 ohm
|   slope of the pullup table from 0 to 0.495 V, typ, clamps not added: 33.5 ohm
|   GND clamp passes 1 mA (typ) near -0.51 V on its own axis
|   POWER clamp passes 1 mA (typ) near -0.81 V on its own axis
|   falling waveform, R_fixture 1000000.0, C_fixture 300.0e-12, V_fixture 3.3V: 20-80 % time 95.3ns typ, 190ns min, 58.2ns max; typ from 3.3 V to 0 V
|   rising waveform, R_fixture 1000000.0, C_fixture 300.0e-12, V_fixture 0V: 20-80 % time 104ns typ, 214ns min, 64.3ns max; typ from 0 V to 3.3 V
[POWER Clamp]
-3.3V     4.11A      4.173A     4.072A
-1.09V    352.5mA    415.9mA    314.5mA
-1.05V    284.5mA    347.9mA    246.5mA
-1.01V    216.5mA    279.9mA    178.5mA
-920mV    63.51mA    126.9mA    25.85mA
-900mV    31.51mA    92.9mA     9.552mA
-890mV    21.35mA    75.9mA     5.807mA
-870mV    9.804mA    44.01mA    2.146mA
-840mV    3.05mA     18.36mA    482.1uA
-780mV    295.2uA    3.193mA    24.34uA
-660mV    2.775uA    96uA       63.85nA
6.6V      0A         0A         0A
[GND Clamp]
-3.3V     -4.155A    -4.23A     -4.11A
-1.06V    -347.4mA   -421.9mA   -301.9mA
-940mV    -143.4mA   -217.9mA   -97.86mA
-910mV    -92.43mA   -166.9mA   -46.86mA
-890mV    -58.43mA   -132.9mA   -25.36mA
-860mV    -25.79mA   -81.93mA   -14.41mA
-840mV    -17.12mA   -51.2mA    -11.69mA
-820mV    -12.64mA   -32.88mA   -10.09mA
-780mV    -8.566mA   -15.84mA   -7.959mA
-700mV    -5.102mA   -6.6mA     -4.73mA
-230mV    -826nA     -13.68uA   -47.8nA
6.6V      45.45nA    5.674uA    302.2pA
| variable   typ   min   max
[Pullup Reference] 3.3V 2.7V 3.6V
| variable   typ   min   max
[Pulldown Reference] 0V 0V 0V
[Pullup]
-3.3V     25.24mA    18.8mA     28.78mA
-910mV    25.24mA    18.8mA     28.78mA
-840mV    25.24mA    18.8mA     26.57mA
-690mV    20.73mA    18.8mA     21.82mA
1.42V     -42.05mA   -37.16mA   -44.57mA
2.24V     -65.72mA   -57.03mA   -69.96mA
2.95V     -85.76mA   -72.68mA   -91.71mA
3.3V      -95.45mA   -77.46mA   -102.3mA
3.75V     -107.5mA   -77.78mA   -115.9mA
4.13V     -112.2mA   -77.78mA   -126.7mA
4.51V     -112.5mA   -77.78mA   -131.2mA
6.6V      -112.5mA   -77.78mA   -131.2mA
[Pulldown]
-3.3V     -20.11mA   -16.83mA   -21.58mA
-910mV    -20.11mA   -16.83mA   -21.58mA
-590mV    -16.45mA   -14.19mA   -17.64mA
-350mV    -10.6mA    -9.483mA   -11.12mA
830mV     25.04mA    22.32mA    26.31mA
1.65V     49.37mA    43.23mA    52.08mA
2.83V     83.46mA    69.8mA     88.71mA
3.3V      96.63mA    78.09mA    103.1mA
3.58V     104.3mA    81.65mA    111.6mA
4.21V     121.2mA    81.65mA    130.6mA
4.53V     121.2mA    81.65mA    140.2mA
6.6V      121.2mA    81.65mA    140.2mA
[Ramp]
dV/dt_r 1.97993V/76.17885ns 1.61994V/213.64203ns 2.15993V/64.30161ns
dV/dt_f 1.97993V/95.80776ns 1.61994V/190.48788ns 2.15993V/59.59596ns
R_load = 1000000.0
| Removed startup time: 0s 0s 0s  .
| Removed end time: 548.5ns.
[Falling Waveform]
R_fixture   = 1000000.0
C_fixture   = 300.0e-12
V_fixture   = 3.3V
V_fixture_min = 2.7V
V_fixture_max = 3.6V
0s        3.3V       2.7V       3.6V
54.2ns    3.304V     2.7V       3.532V
92.3ns    2.845V     2.693V     2.44V
129.6ns   2.264V     2.527V     892.9mV
171.9ns   1.207V     2.249V     70.54mV
212.9ns   494mV      2.002V     1.486mV
262.4ns   39.51mV    1.608V     146.7uV
397.5ns   113uV      420.2mV    114uV
472ns     109.5uV    74.05mV    113.5uV
548.7ns   108.7uV    99.57uV    113.2uV
| Removed startup time: 0s 0s 0s  .
| Removed end time: 582.9ns.
[Rising Waveform]
R_fixture   = 1000000.0
C_fixture   = 300.0e-12
V_fixture   = 0V
V_fixture_min = 0V
V_fixture_max = 0V
0s        21.36nV    1.066uV    17.12nV
33.4ns    12.56mV    1.472mV    28.98mV
57.3ns    153.9mV    27.3mV     364.1mV
93.9ns    590.1mV    145.3mV    1.227V
136.9ns   1.211V     363.6mV    2.848V
178.3ns   2.186V     583.6mV    3.524V
221.6ns   2.874V     832.5mV    3.598V
273.3ns   3.26V      1.224V     3.6V
432.6ns   3.3V       2.422V     3.6V
583.1ns   3.3V       2.7V       3.6V
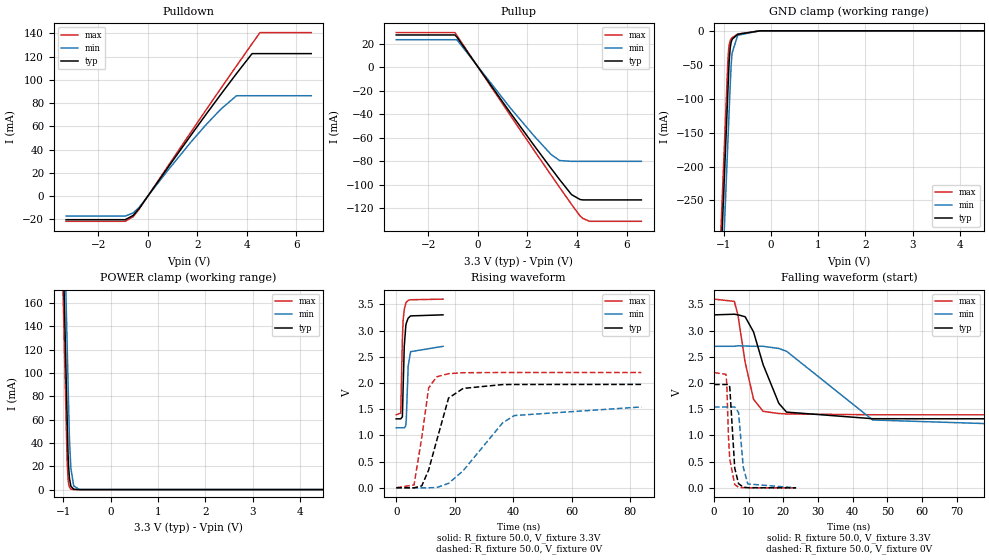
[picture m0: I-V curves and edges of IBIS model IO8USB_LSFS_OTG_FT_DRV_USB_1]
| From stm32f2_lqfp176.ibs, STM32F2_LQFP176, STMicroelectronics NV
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| *** New cell (Generated with 5.14beta1 (Sep 20 2010 13:23:23))
[Model]   IO8USB_LSFS_OTG_FT_DRV_USB_1
Model_type 3-state
Polarity   Non-Inverting
Enable   Active-Low
| CAP_THRESHOLD on pad DPV33 is "CMOS" :
| Rising=10.0% of vddio   Falling=90.0% of vddio
| C_comp min and max val. don't necessarily correlate with the min and max pvt
| but are the smallest and greatest pad capacitance found.
| var   typ   min   max
C_comp   5.85005pF  5.57930pF  6.38630pF
Vmeas = 1.65V   | Reference voltage for timing measurements
Cref  = 400.0pF   | Timing specification test load capacitance value
Rref  = 1.0MOhm   | Timing specification test load resistance value
Vref  = 1.65V   | Timing specification test load voltage
[Model Spec]
| variable   typ   min   max
[Temperature Range] 25.0 125.0 -40.0
| variable   typ   min   max
[Voltage Range] 3.3V 2.7V 3.6V
| variable   typ   min   max
[POWER Clamp Reference] 3.3V 2.7V 3.6V
| variable   typ   min   max
[GND Clamp Reference] 0V 0V 0V
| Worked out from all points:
|   slope of the pulldown table from 0 to 0.495 V, typ, clamps not added: 32.9 ohm
|   slope of the pullup table from 0 to 0.495 V, typ, clamps not added: 33.4 ohm
|   GND clamp passes 1 mA (typ) near -0.51 V on its own axis
|   POWER clamp passes 1 mA (typ) near -0.81 V on its own axis
|   rising waveform, R_fixture 50.0, V_fixture 3.3V: 20-80 % time 635ps typ, 643ps min, 624ps max; typ from 1.31 V to 3.3 V
|   falling waveform, R_fixture 50.0, V_fixture 3.3V: 20-80 % time 6.23ns typ, 14.8ns min, 3.63ns max; typ from 3.3 V to 1.31 V
|   rising waveform, R_fixture 50.0, V_fixture 0V: 20-80 % time 5.65ns typ, 13.7ns min, 3.2ns max; typ from 0 V to 1.97 V
|   falling waveform, R_fixture 50.0, V_fixture 0V: 20-80 % time 1.02ns typ, 1.24ns min, 910ps max; typ from 1.97 V to 0 V
[POWER Clamp]
-3.3V     4.11A      4.173A     4.072A
-1.09V    352.5mA    415.9mA    314.5mA
-1.05V    284.5mA    347.9mA    246.5mA
-1.01V    216.5mA    279.9mA    178.5mA
-920mV    63.51mA    126.9mA    25.85mA
-900mV    31.51mA    92.9mA     9.552mA
-890mV    21.35mA    75.9mA     5.807mA
-870mV    9.804mA    44.01mA    2.146mA
-840mV    3.05mA     18.36mA    482.1uA
-780mV    295.2uA    3.193mA    24.34uA
-660mV    2.775uA    96uA       63.85nA
6.6V      0A         0A         0A
[GND Clamp]
-3.3V     -4.155A    -4.23A     -4.11A
-1.06V    -347.4mA   -421.9mA   -301.9mA
-940mV    -143.4mA   -217.9mA   -97.86mA
-910mV    -92.43mA   -166.9mA   -46.86mA
-890mV    -58.43mA   -132.9mA   -25.36mA
-880mV    -43.4mA    -115.9mA   -20.1mA
-860mV    -25.79mA   -81.93mA   -14.41mA
-840mV    -17.12mA   -51.2mA    -11.69mA
-820mV    -12.64mA   -32.88mA   -10.09mA
-700mV    -5.102mA   -6.6mA     -4.73mA
-230mV    -826nA     -13.68uA   -47.8nA
6.6V      45.45nA    5.674uA    302.2pA
| variable   typ   min   max
[Pullup Reference] 3.3V 2.7V 3.6V
| variable   typ   min   max
[Pulldown Reference] 0V 0V 0V
[Pullup]
-3.3V     27.39mA    23.34mA    29.42mA
-930mV    27.39mA    23.34mA    29.42mA
-850mV    25.58mA    23.34mA    26.89mA
1.3V      -38.62mA   -34.52mA   -40.84mA
2.24V     -65.89mA   -57.92mA   -69.99mA
2.95V     -86.03mA   -74.23mA   -91.74mA
3.3V      -95.77mA   -79.51mA   -102.4mA
3.78V     -108.5mA   -80.16mA   -116.8mA
4.13V     -112.7mA   -80.16mA   -126.8mA
4.25V     -113mA     -80.16mA   -128.9mA
4.51V     -113mA     -80.16mA   -131.2mA
6.6V      -113mA     -80.16mA   -131.2mA
[Pulldown]
-3.3V     -20.23mA   -17.13mA   -21.61mA
-910mV    -20.23mA   -17.13mA   -21.61mA
-590mV    -16.53mA   -14.4mA    -17.67mA
-350mV    -10.65mA   -9.611mA   -11.14mA
830mV     25.16mA    22.7mA     26.35mA
1.77V     53.21mA    47.2mA     55.94mA
2.36V     70.51mA    61.59mA    74.34mA
2.95V     87.51mA    74.76mA    92.6mA
3.58V     105.3mA    86.31mA    111.9mA
4.21V     122.5mA    86.31mA    131mA
4.53V     122.5mA    86.31mA    140.6mA
6.6V      122.5mA    86.31mA    140.6mA
[Ramp]
dV/dt_r 1.18334V/5.6521ns 925.4173mV/13.69369ns 1.31966V/3.19776ns
dV/dt_f 1.19111V/6.23394ns 932.79078mV/14.75204ns 1.32391V/3.62958ns
R_load = 50.0
| Removed startup time: 0s 0s 0s  .
| Removed end time: 16.005ns.
[Rising Waveform]
R_fixture   = 50.0
V_fixture   = 3.3V
V_fixture_min = 2.7V
V_fixture_max = 3.6V
0s        1.315V     1.145V     1.393V
1.55ns    1.315V     1.145V     1.426V
2.115ns   1.354V     1.145V     2.844V
2.375ns   1.919V     1.145V     3.2V
2.76ns    2.701V     1.145V     3.405V
3.285ns   3.092V     1.185V     3.519V
3.455ns   3.14V      1.309V     3.54V
4.09ns    3.236V     2.318V     3.575V
4.915ns   3.28V      2.597V     3.588V
16.02ns   3.3V       2.699V     3.6V
| Removed startup time: 0s 0s 0s  .
| Removed end time: 116.22ns.
[Falling Waveform]
R_fixture   = 50.0
V_fixture   = 3.3V
V_fixture_min = 2.7V
V_fixture_max = 3.6V
0s        3.3V       2.7V       3.6V
5.85ns    3.312V     2.7V       3.557V
6.9ns     3.301V     2.71V      3.291V
8.97ns    3.264V     2.706V     2.394V
11.4ns    2.973V     2.7V       1.689V
14.16ns   2.35V      2.7V       1.459V
18.69ns   1.612V     2.659V     1.418V
20.91ns   1.445V     2.606V     1.41V
45.78ns   1.319V     1.295V     1.394V
116.3ns   1.315V     1.145V     1.393V
| Removed startup time: 0s 0s 0s  .
| Removed end time: 83.86ns.
[Rising Waveform]
R_fixture   = 50.0
V_fixture   = 0V
V_fixture_min = 0V
V_fixture_max = 0V
0s        27.47nV    622nV      12.01nV
6.1ns     -2.19mV    -779.9uV   53.46mV
8.76ns    36.47mV    -860.5uV   964.4mV
11.1ns    339.6mV    -875uV     1.904V
13.82ns   893.4mV    3.516mV    2.117V
17.92ns   1.712V     83.44mV    2.177V
22.92ns   1.896V     324.8mV    2.196V
36.4ns    1.969V     1.238V     2.199V
40.38ns   1.971V     1.378V     2.199V
83.9ns    1.972V     1.542V     2.199V
| Removed startup time: 0s 0s 0s  .
| Removed end time: 23.67ns.
[Falling Waveform]
R_fixture   = 50.0
V_fixture   = 0V
V_fixture_min = 0V
V_fixture_max = 0V
0s        1.972V     1.542V     2.199V
3.43ns    1.972V     1.542V     2.166V
3.65ns    1.972V     1.542V     2.005V
4.13ns    1.975V     1.542V     1.013V
4.525ns   1.927V     1.542V     549.1mV
5.965ns   376.5mV    1.543V     61.94mV
7.065ns   80.34mV    1.438V     12.44mV
8.43ns    13.51mV    391mV      3.352mV
9.73ns    3.365mV    74.48mV    952uV
23.68ns   30.71uV    81.44uV    2.944uV
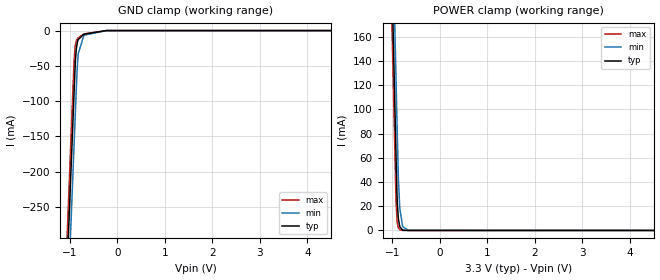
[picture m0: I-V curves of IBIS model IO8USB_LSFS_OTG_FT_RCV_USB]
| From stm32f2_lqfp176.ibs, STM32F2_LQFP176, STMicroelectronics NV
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| *** New cell (Generated with 5.14beta1 (Sep 20 2010 13:23:23))
[Model]   IO8USB_LSFS_OTG_FT_RCV_USB
Model_type Input
Polarity   Non-Inverting
Enable   Active-Low
| CAP_THRESHOLD on pad DNV33 is "CMOS" :
| Rising=10.0% of vddio   Falling=90.0% of vddio
| C_comp min and max val. don't necessarily correlate with the min and max pvt
| but are the smallest and greatest pad capacitance found.
| var   typ   min   max
C_comp   5.83500pF  5.56170pF  6.37065pF
Vinl = 810.0mV | Dummy value overriden by next lines
Vinh = 2.52V | Dummy value overriden by next lines
[Model Spec]
| TIME_THRESHOLD on pin ZIPV12 is "CORE" :
| Rising=40.0% of vdd   Falling=60.0% of vdd
Vinl 1.25450V 1.03850V 1.36250V
Vinh 1.66150V 1.36950V 1.82450V
| variable   typ   min   max
[Temperature Range] 25.0 125.0 -40.0
| variable   typ   min   max
[Voltage Range] 3.3V 2.7V 3.6V
| variable   typ   min   max
[POWER Clamp Reference] 3.3V 2.7V 3.6V
| variable   typ   min   max
[GND Clamp Reference] 0V 0V 0V
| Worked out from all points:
|   GND clamp passes 1 mA (typ) near -0.51 V on its own axis
|   POWER clamp passes 1 mA (typ) near -0.81 V on its own axis
[POWER Clamp]
-3.3V     4.11A      4.173A     4.072A
-1.09V    352.5mA    415.9mA    314.5mA
-1.05V    284.5mA    347.9mA    246.5mA
-1.01V    216.5mA    279.9mA    178.5mA
-920mV    63.51mA    126.9mA    25.85mA
-900mV    31.51mA    92.9mA     9.552mA
-890mV    21.35mA    75.9mA     5.807mA
-870mV    9.804mA    44.01mA    2.146mA
-840mV    3.05mA     18.36mA    482.1uA
-780mV    295.2uA    3.193mA    24.34uA
-660mV    2.775uA    96uA       63.85nA
6.6V      0A         0A         0A
[GND Clamp]
-3.3V     -4.155A    -4.23A     -4.11A
-1.06V    -347.4mA   -421.9mA   -301.9mA
-940mV    -143.4mA   -217.9mA   -97.86mA
-910mV    -92.43mA   -166.9mA   -46.86mA
-890mV    -58.43mA   -132.9mA   -25.36mA
-880mV    -43.4mA    -115.9mA   -20.1mA
-860mV    -25.79mA   -81.93mA   -14.41mA
-840mV    -17.12mA   -51.2mA    -11.69mA
-820mV    -12.64mA   -32.88mA   -10.09mA
-700mV    -5.102mA   -6.6mA     -4.73mA
-230mV    -826nA     -13.68uA   -47.8nA
6.6V      45.45nA    5.674uA    302.2pA
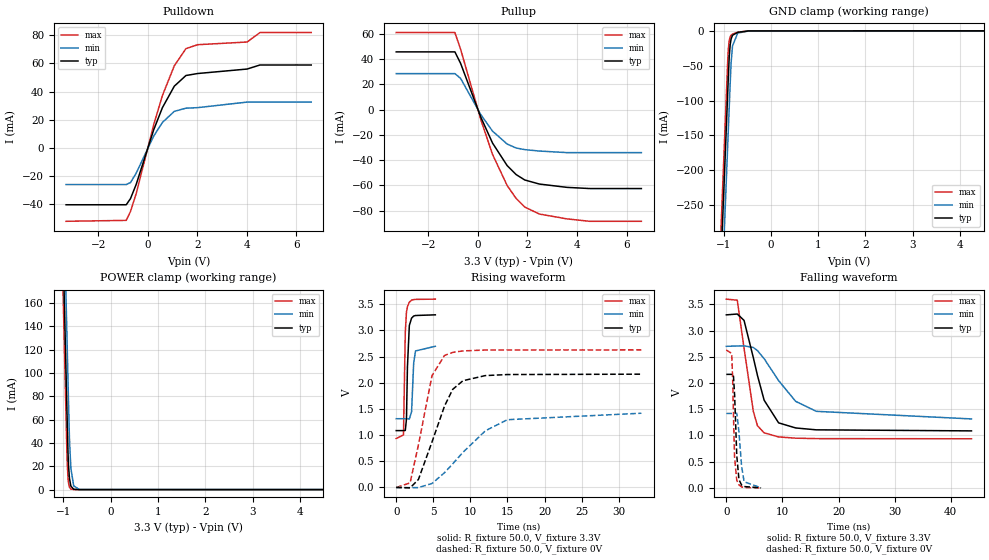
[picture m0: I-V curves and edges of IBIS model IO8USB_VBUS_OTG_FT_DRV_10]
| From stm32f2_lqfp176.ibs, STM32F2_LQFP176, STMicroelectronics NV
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| *** New cell (Generated with 5.14beta1 (Sep 20 2010 13:23:23))
[Model]   IO8USB_VBUS_OTG_FT_DRV_10
Model_type 3-state
Polarity   Non-Inverting
Enable   Active-Low
| CAP_THRESHOLD on pad IOV33 is "CMOS" :
| Rising=10.0% of vddio   Falling=90.0% of vddio
| C_comp min and max val. don't necessarily correlate with the min and max pvt
| but are the smallest and greatest pad capacitance found.
| var   typ   min   max
C_comp   2.70355pF  2.58515pF  2.87890pF
Vmeas = 1.65V   | Reference voltage for timing measurements
Cref  = 50.0pF   | Timing specification test load capacitance value
Rref  = 10.0MOhm   | Timing specification test load resistance value
Vref  = 1.65V   | Timing specification test load voltage
[Model Spec]
| variable   typ   min   max
[Temperature Range] 25.0 125.0 -40.0
| variable   typ   min   max
[Voltage Range] 3.3V 2.7V 3.6V
| variable   typ   min   max
[POWER Clamp Reference] 3.3V 2.7V 3.6V
| variable   typ   min   max
[GND Clamp Reference] 0V 0V 0V
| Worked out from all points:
|   slope of the pulldown table from 0 to 0.495 V, typ, clamps not added: 20 ohm
|   slope of the pullup table from 0 to 0.495 V, typ, clamps not added: 21.7 ohm
|   GND clamp passes 1 mA (typ) near -0.61 V on its own axis
|   POWER clamp passes 1 mA (typ) near -0.81 V on its own axis
|   rising waveform, R_fixture 50.0, V_fixture 3.3V: 20-80 % time 203ps typ, 245ps min, 189ps max; typ from 1.09 V to 3.3 V
|   falling waveform, R_fixture 50.0, V_fixture 3.3V: 20-80 % time 3.19ns typ, 6.12ns min, 2.09ns max; typ from 3.3 V to 1.09 V
|   rising waveform, R_fixture 50.0, V_fixture 0V: 20-80 % time 3.25ns typ, 6.02ns min, 2.15ns max; typ from 0 V to 2.17 V
|   falling waveform, R_fixture 50.0, V_fixture 0V: 20-80 % time 463ps typ, 656ps min, 373ps max; typ from 2.17 V to 0.001 V
[POWER Clamp]
-3.3V     4.11A      4.173A     4.072A
-1.09V    352.5mA    415.9mA    314.5mA
-1.05V    284.5mA    347.9mA    246.5mA
-1.01V    216.5mA    279.9mA    178.5mA
-920mV    63.51mA    126.9mA    25.85mA
-900mV    31.51mA    92.9mA     9.552mA
-890mV    21.35mA    75.9mA     5.807mA
-870mV    9.804mA    44.01mA    2.146mA
-840mV    3.05mA     18.36mA    482.1uA
-780mV    295.2uA    3.193mA    24.34uA
-660mV    2.764uA    96.47uA    62.42nA
6.6V      0A         0A         0A
[GND Clamp]
-3.3V     -4.149A    -4.224A    -4.103A
-1.06V    -341.2mA   -416.1mA   -295.1mA
-940mV    -137.2mA   -212.1mA   -91.08mA
-910mV    -86.19mA   -161.1mA   -40.08mA
-900mV    -69.19mA   -144.1mA   -27.04mA
-880mV    -37.32mA   -110.1mA   -13.88mA
-860mV    -20.03mA   -76.14mA   -8.588mA
-840mV    -11.71mA   -45.57mA   -6.266mA
-810mV    -6.348mA   -21.68mA   -4.67mA
-700mV    -2.155mA   -3.174mA   -2.051mA
-470mV    -142.2uA   -334.3uA   -67.55uA
6.6V      13.96nA    1.746uA    94.44pA
| variable   typ   min   max
[Pullup Reference] 3.3V 2.7V 3.6V
| variable   typ   min   max
[Pulldown Reference] 0V 0V 0V
[Pullup]
-3.3V     45.78mA    28.54mA    61.09mA
-930mV    45.78mA    28.54mA    61.09mA
-700mV    36.69mA    24.76mA    47.9mA
120mV     -6.142mA   -4.065mA   -8.189mA
590mV     -26.5mA    -17.07mA   -35.52mA
1.18V     -44.36mA   -27.27mA   -60.11mA
1.54V     -51.43mA   -30.39mA   -70.35mA
1.89V     -55.75mA   -31.69mA   -77.18mA
2.48V     -58.98mA   -32.83mA   -82.75mA
3.6V      -61.62mA   -34.07mA   -86.61mA
4.51V     -62.54mA   -34.07mA   -88.51mA
6.6V      -62.54mA   -34.07mA   -88.51mA
[Pulldown]
-3.3V     -40.26mA   -25.94mA   -51.99mA
-870mV    -40.25mA   -25.94mA   -51.33mA
-700mV    -35.92mA   -24.51mA   -45.06mA
-470mV    -25.89mA   -17.87mA   -32.39mA
240mV     12.97mA    8.52mA     16.62mA
590mV     28.62mA    18.11mA    37.2mA
1.07V     43.85mA    26mA       58.31mA
1.54V     51.42mA    28.24mA    70.48mA
2.01V     52.82mA    28.63mA    73.27mA
4.01V     56.01mA    32.56mA    75.18mA
4.53V     58.89mA    32.56mA    81.88mA
6.6V      58.89mA    32.56mA    81.88mA
[Ramp]
dV/dt_r 1.29886V/3.25005ns 851.30589mV/6.02473ns 1.57728V/2.15393ns
dV/dt_f 1.32782V/3.1895ns 831.60148mV/6.13532ns 1.59819V/2.09353ns
R_load = 50.0
| Removed startup time: 0s 0s 0s  .
| Removed end time: 5.273ns.
[Rising Waveform]
R_fixture   = 50.0
V_fixture   = 3.3V
V_fixture_min = 2.7V
V_fixture_max = 3.6V
0s        1.087V     1.314V     936.3mV
980ps     1.087V     1.314V     1.005V
1.224ns   1.09V      1.314V     2.959V
1.384ns   1.308V     1.314V     3.352V
1.514ns   2.303V     1.314V     3.454V
1.77ns    3.096V     1.309V     3.541V
2.073ns   3.236V     1.448V     3.58V
2.353ns   3.276V     2.371V     3.59V
2.605ns   3.286V     2.609V     3.594V
5.275ns   3.299V     2.698V     3.599V
| Removed startup time: 0s 0s 0s  .
| Removed end time: 43.69ns.
[Falling Waveform]
R_fixture   = 50.0
V_fixture   = 3.3V
V_fixture_min = 2.7V
V_fixture_max = 3.6V
0s        3.3V       2.7V       3.6V
1.95ns    3.316V     2.706V     3.58V
3.155ns   3.195V     2.709V     2.667V
4.81ns    2.485V     2.678V     1.46V
5.555ns   2.142V     2.617V     1.184V
6.74ns    1.672V     2.464V     1.05V
9.32ns    1.24V      2.046V     971.9mV
12.36ns   1.143V     1.65V      947.9mV
16.04ns   1.107V     1.46V      939.7mV
43.7ns    1.087V     1.315V     936.3mV
| Removed startup time: 0s 0s 0s  .
| Removed end time: 33.05ns.
[Rising Waveform]
R_fixture   = 50.0
V_fixture   = 0V
V_fixture_min = 0V
V_fixture_max = 0V
0s        10.15nV    410.7nV    7.11nV
1.875ns   -7.057mV   -2.649mV   88.14mV
2.995ns   153.3mV    -2.219mV   811.6mV
4.825ns   869.2mV    76.56mV    2.136V
6.52ns    1.558V     283.2mV    2.523V
7.625ns   1.876V     452.4mV    2.581V
9ns       2.04V      672mV      2.61V
12.01ns   2.138V     1.082V     2.626V
14.99ns   2.158V     1.295V     2.628V
33.06ns   2.165V     1.419V     2.629V
| Removed startup time: 0s 0s 0s  .
| Removed end time: 6.183ns.
[Falling Waveform]
R_fixture   = 50.0
V_fixture   = 0V
V_fixture_min = 0V
V_fixture_max = 0V
0s        2.165V     1.419V     2.629V
953ps     2.165V     1.419V     2.565V
1.139ns   2.171V     1.419V     2.043V
1.27ns    2.132V     1.418V     1.378V
1.476ns   1.772V     1.419V     574.2mV
1.861ns   613.7mV    1.424V     143.1mV
2.248ns   158.9mV    1.07V      58.11mV
2.716ns   54.24mV    417.6mV    19.6mV
3.17ns    25.44mV    116.8mV    5.577mV
6.185ns   504.7uV    1.203mV    351.2uV
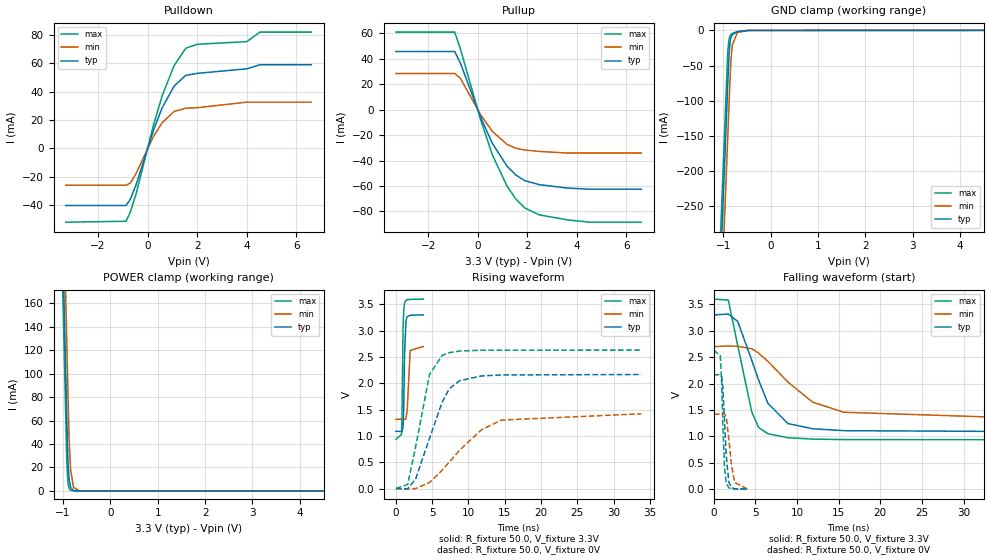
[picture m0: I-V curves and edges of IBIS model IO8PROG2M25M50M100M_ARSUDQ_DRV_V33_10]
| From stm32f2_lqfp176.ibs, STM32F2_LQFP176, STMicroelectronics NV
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| *** New cell (Generated with 5.14beta1 (Sep 20 2010 13:23:23))
[Model]   IO8PROG2M25M50M100M_ARSUDQ_DRV_V33_10
Model_type 3-state
Polarity   Non-Inverting
Enable   Active-Low
| CAP_THRESHOLD on pad IOV33 is "CMOS" :
| Rising=10.0% of vddio   Falling=90.0% of vddio
| C_comp min and max val. don't necessarily correlate with the min and max pvt
| but are the smallest and greatest pad capacitance found.
| var   typ   min   max
C_comp   2.14295pF  2.03740pF  2.26750pF
Vmeas = 1.65V   | Reference voltage for timing measurements
Cref  = 50.0pF   | Timing specification test load capacitance value
Rref  = 1.0MOhm   | Timing specification test load resistance value
Vref  = 1.65V   | Timing specification test load voltage
[Model Spec]
| variable   typ   min   max
[Temperature Range] 25.0 125.0 -40.0
| variable   typ   min   max
[Voltage Range] 3.3V 2.7V 3.6V
| variable   typ   min   max
[POWER Clamp Reference] 3.3V 2.7V 3.6V
| variable   typ   min   max
[GND Clamp Reference] 0V 0V 0V
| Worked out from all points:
|   slope of the pulldown table from 0 to 0.495 V, typ, clamps not added: 20 ohm
|   slope of the pullup table from 0 to 0.495 V, typ, clamps not added: 21.7 ohm
|   GND clamp passes 1 mA (typ) near -0.62 V on its own axis
|   POWER clamp passes 1 mA (typ) near -0.81 V on its own axis
|   rising waveform, R_fixture 50.0, V_fixture 3.3V: 20-80 % time 162ps typ, 212ps min, 146ps max; typ from 1.09 V to 3.3 V
|   falling waveform, R_fixture 50.0, V_fixture 3.3V: 20-80 % time 3.16ns typ, 6.11ns min, 2.07ns max; typ from 3.3 V to 1.09 V
|   rising waveform, R_fixture 50.0, V_fixture 0V: 20-80 % time 3.26ns typ, 6.05ns min, 2.15ns max; typ from 0 V to 2.17 V
|   falling waveform, R_fixture 50.0, V_fixture 0V: 20-80 % time 416ps typ, 600ps min, 330ps max; typ from 2.17 V to 0.001 V
[POWER Clamp]
-3.3V     4.11A      4.173A     4.072A
-1.09V    352.5mA    415.9mA    314.5mA
-1.05V    284.5mA    347.9mA    246.5mA
-1.01V    216.5mA    279.9mA    178.5mA
-920mV    63.51mA    126.9mA    25.85mA
-900mV    31.51mA    92.9mA     9.552mA
-890mV    21.35mA    75.9mA     5.807mA
-870mV    9.804mA    44.01mA    2.146mA
-840mV    3.05mA     18.36mA    482.1uA
-780mV    295.2uA    3.194mA    24.34uA
-660mV    2.764uA    96.54uA    62.42nA
6.6V      0A         0A         0A
[GND Clamp]
-3.3V     -4.149A    -4.223A    -4.103A
-1.06V    -340.6mA   -415.4mA   -294.5mA
-940mV    -136.6mA   -211.4mA   -90.54mA
-910mV    -85.55mA   -160.4mA   -39.54mA
-900mV    -68.55mA   -143.4mA   -26.55mA
-880mV    -36.73mA   -109.4mA   -13.46mA
-860mV    -19.54mA   -75.4mA    -8.234mA
-840mV    -11.29mA   -44.89mA   -5.954mA
-810mV    -6.008mA   -21.13mA   -4.401mA
-700mV    -1.958mA   -2.906mA   -1.882mA
-470mV    -105.5uA   -263.9uA   -47.31uA
6.6V      9.456nA    1.185uA    63.86pA
| variable   typ   min   max
[Pullup Reference] 3.3V 2.7V 3.6V
| variable   typ   min   max
[Pulldown Reference] 0V 0V 0V
[Pullup]
-3.3V     45.75mA    28.49mA    61.06mA
-930mV    45.75mA    28.49mA    61.06mA
-700mV    36.68mA    24.75mA    47.89mA
120mV     -6.142mA   -4.065mA   -8.189mA
590mV     -26.5mA    -17.07mA   -35.52mA
1.18V     -44.36mA   -27.27mA   -60.11mA
1.54V     -51.43mA   -30.39mA   -70.35mA
1.89V     -55.75mA   -31.69mA   -77.18mA
2.48V     -58.98mA   -32.83mA   -82.75mA
3.6V      -61.62mA   -34.07mA   -86.61mA
4.51V     -62.54mA   -34.07mA   -88.51mA
6.6V      -62.54mA   -34.07mA   -88.51mA
[Pulldown]
-3.3V     -40.26mA   -25.94mA   -51.99mA
-870mV    -40.25mA   -25.94mA   -51.33mA
-700mV    -35.92mA   -24.51mA   -45.06mA
-470mV    -25.89mA   -17.87mA   -32.39mA
240mV     12.97mA    8.52mA     16.62mA
590mV     28.62mA    18.11mA    37.2mA
1.07V     43.85mA    26mA       58.31mA
1.54V     51.42mA    28.24mA    70.48mA
2.01V     52.82mA    28.63mA    73.27mA
4.01V     56.01mA    32.54mA    75.18mA
4.53V     58.87mA    32.54mA    81.86mA
6.6V      58.87mA    32.54mA    81.86mA
[Ramp]
dV/dt_r 1.29886V/3.25797ns 851.30598mV/6.04631ns 1.57728V/2.15286ns
dV/dt_f 1.32782V/3.1571ns 831.60155mV/6.12313ns 1.59819V/2.06871ns
R_load = 50.0
| Removed startup time: 0s 0s 0s  .
| Removed end time: 3.764ns.
[Rising Waveform]
R_fixture   = 50.0
V_fixture   = 3.3V
V_fixture_min = 2.7V
V_fixture_max = 3.6V
0s        1.087V     1.314V     936.3mV
773ps     1.084V     1.314V     1.027V
828ps     1.083V     1.314V     1.316V
985ps     1.167V     1.313V     3.047V
1.068ns   1.475V     1.313V     3.364V
1.182ns   2.518V     1.31V      3.518V
1.385ns   3.186V     1.326V     3.577V
1.561ns   3.267V     1.505V     3.586V
1.965ns   3.291V     2.622V     3.592V
3.766ns   3.298V     2.698V     3.598V
| Removed startup time: 0s 0s 0s  .
| Removed end time: 43.195ns.
[Falling Waveform]
R_fixture   = 50.0
V_fixture   = 3.3V
V_fixture_min = 2.7V
V_fixture_max = 3.6V
0s        3.3V       2.7V       3.6V
1.745ns   3.316V     2.711V     3.58V
2.87ns    3.178V     2.707V     2.723V
4.56ns    2.44V      2.659V     1.464V
5.385ns   2.065V     2.578V     1.168V
6.5ns     1.626V     2.42V      1.05V
8.91ns    1.242V     2.028V     974.2mV
11.86ns   1.145V     1.649V     948.6mV
15.6ns    1.108V     1.457V     939.8mV
43.21ns   1.087V     1.315V     936.3mV
| Removed startup time: 0s 0s 0s  .
| Removed end time: 33.81ns.
[Rising Waveform]
R_fixture   = 50.0
V_fixture   = 0V
V_fixture_min = 0V
V_fixture_max = 0V
0s        7.743nV    280.7nV    5.712nV
1.615ns   -4.243mV   -12.29mV   77.53mV
2.72ns    183mV      715.5uV    795.8mV
4.625ns   951.6mV    113.6mV    2.162V
6.365ns   1.637V     347.3mV    2.528V
7.34ns    1.892V     500.5mV    2.58V
8.78ns    2.048V     728.1mV    2.611V
11.79ns   2.138V     1.117V     2.626V
14.56ns   2.157V     1.3V       2.628V
33.82ns   2.165V     1.419V     2.629V
| Removed startup time: 0s 0s 0s  .
| Removed end time: 4.05ns.
[Falling Waveform]
R_fixture   = 50.0
V_fixture   = 0V
V_fixture_min = 0V
V_fixture_max = 0V
0s        2.165V     1.419V     2.629V
777ps     2.17V      1.418V     2.535V
944ps     2.139V     1.419V     2.022V
1.093ns   1.925V     1.421V     1.206V
1.291ns   1.291V     1.428V     411.7mV
1.502ns   624.7mV    1.369V     113.2mV
1.819ns   125.5mV    927.1mV    23.97mV
2.146ns   27.87mV    438.6mV    8.707mV
2.513ns   8.597mV    127.1mV    4.158mV
4.052ns   827uV      1.52mV     576.9uV
